VERSION 5.8 ;
BUSBITCHARS "[]" ;
DIVIDERCHAR "/" ;
UNITS
    DATABASE MICRONS 1000 ;
END UNITS

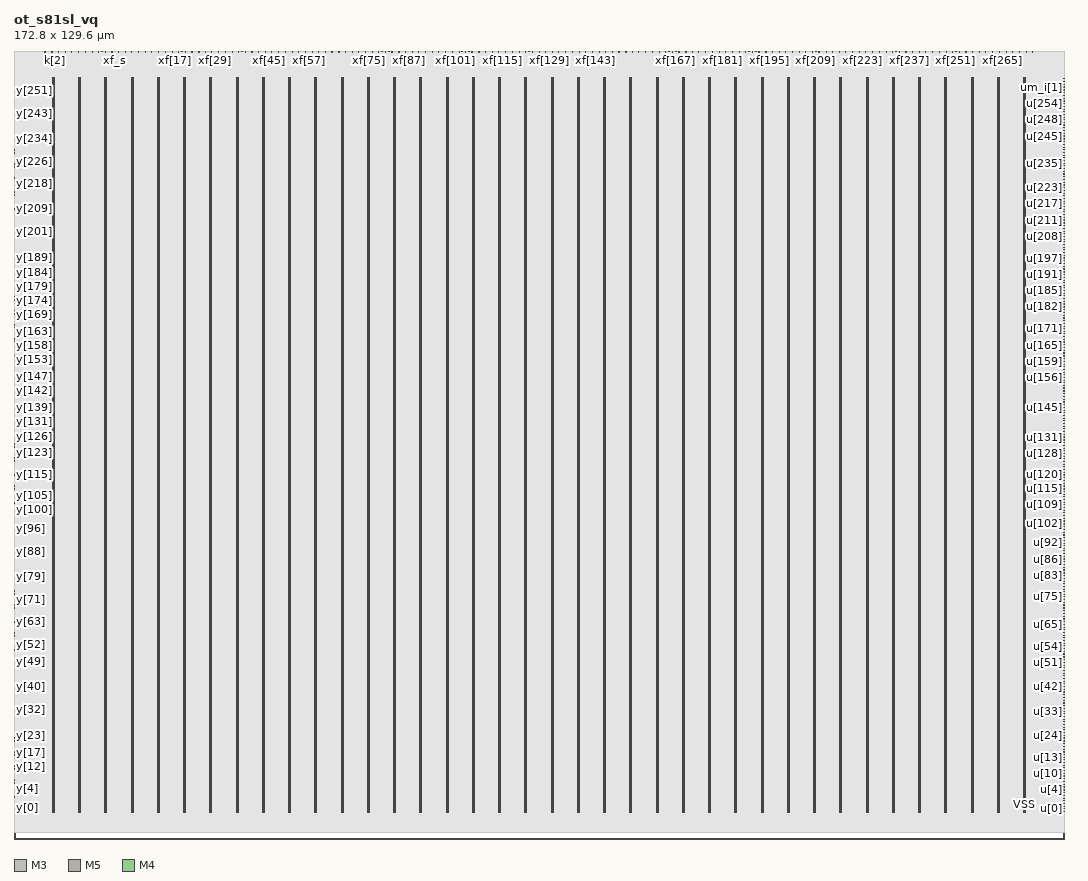
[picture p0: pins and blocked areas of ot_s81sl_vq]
MACRO ot_s81sl_vq
  FOREIGN ot_s81sl_vq 0 0 ;
  CLASS BLOCK ;
  SIZE 172.8 BY 129.6 ;
  PIN clk
    DIRECTION INPUT ;
    USE SIGNAL ;
    PORT
      LAYER M3 ;
        RECT  4.608 129.562 4.626 129.6 ;
    END
  END clk
  PIN fault
    DIRECTION OUTPUT ;
    USE SIGNAL ;
    PORT
      LAYER M3 ;
        RECT  15.552 129.562 15.57 129.6 ;
    END
  END fault
  PIN k[0]
    DIRECTION INPUT ;
    USE SIGNAL ;
    PORT
      LAYER M3 ;
        RECT  5.688 129.562 5.706 129.6 ;
    END
  END k[0]
  PIN k[1]
    DIRECTION INPUT ;
    USE SIGNAL ;
    PORT
      LAYER M5 ;
        RECT  6.24 129.516 6.264 129.6 ;
    END
  END k[1]
  PIN k[2]
    DIRECTION INPUT ;
    USE SIGNAL ;
    PORT
      LAYER M3 ;
        RECT  6.768 129.562 6.786 129.6 ;
    END
  END k[2]
  PIN m_b
    DIRECTION INPUT ;
    USE SIGNAL ;
    PORT
      LAYER M5 ;
        RECT  10.656 129.516 10.68 129.6 ;
    END
  END m_b
  PIN m_i[0]
    DIRECTION INPUT ;
    USE SIGNAL ;
    PORT
      LAYER M3 ;
        RECT  11.16 129.562 11.178 129.6 ;
    END
  END m_i[0]
  PIN m_i[1]
    DIRECTION INPUT ;
    USE SIGNAL ;
    PORT
      LAYER M5 ;
        RECT  11.712 129.516 11.736 129.6 ;
    END
  END m_i[1]
  PIN m_i[2]
    DIRECTION INPUT ;
    USE SIGNAL ;
    PORT
      LAYER M3 ;
        RECT  12.24 129.562 12.258 129.6 ;
    END
  END m_i[2]
  PIN m_i[3]
    DIRECTION INPUT ;
    USE SIGNAL ;
    PORT
      LAYER M5 ;
        RECT  12.864 129.516 12.888 129.6 ;
    END
  END m_i[3]
  PIN m_i[4]
    DIRECTION INPUT ;
    USE SIGNAL ;
    PORT
      LAYER M3 ;
        RECT  13.392 129.562 13.41 129.6 ;
    END
  END m_i[4]
  PIN m_i[5]
    DIRECTION INPUT ;
    USE SIGNAL ;
    PORT
      LAYER M5 ;
        RECT  13.92 129.516 13.944 129.6 ;
    END
  END m_i[5]
  PIN m_i[6]
    DIRECTION INPUT ;
    USE SIGNAL ;
    PORT
      LAYER M3 ;
        RECT  14.472 129.562 14.49 129.6 ;
    END
  END m_i[6]
  PIN m_i[7]
    DIRECTION INPUT ;
    USE SIGNAL ;
    PORT
      LAYER M5 ;
        RECT  14.976 129.516 15 129.6 ;
    END
  END m_i[7]
  PIN m_q
    DIRECTION INPUT ;
    USE SIGNAL ;
    PORT
      LAYER M3 ;
        RECT  10.08 129.562 10.098 129.6 ;
    END
  END m_q
  PIN m_v
    DIRECTION INPUT ;
    USE SIGNAL ;
    PORT
      LAYER M5 ;
        RECT  9.504 129.516 9.528 129.6 ;
    END
  END m_v
  PIN rst_n
    DIRECTION INPUT ;
    USE SIGNAL ;
    PORT
      LAYER M5 ;
        RECT  5.088 129.516 5.112 129.6 ;
    END
  END rst_n
  PIN sid[0]
    DIRECTION INPUT ;
    USE SIGNAL ;
    PORT
      LAYER M5 ;
        RECT  7.296 129.516 7.32 129.6 ;
    END
  END sid[0]
  PIN sid[1]
    DIRECTION INPUT ;
    USE SIGNAL ;
    PORT
      LAYER M3 ;
        RECT  7.848 129.562 7.866 129.6 ;
    END
  END sid[1]
  PIN sid[2]
    DIRECTION INPUT ;
    USE SIGNAL ;
    PORT
      LAYER M5 ;
        RECT  8.448 129.516 8.472 129.6 ;
    END
  END sid[2]
  PIN sid[3]
    DIRECTION INPUT ;
    USE SIGNAL ;
    PORT
      LAYER M3 ;
        RECT  9 129.562 9.018 129.6 ;
    END
  END sid[3]
  PIN u[0]
    DIRECTION INPUT ;
    USE SIGNAL ;
    PORT
      LAYER M4 ;
        RECT  172.716 6.336 172.8 6.36 ;
    END
  END u[0]
  PIN u[100]
    DIRECTION INPUT ;
    USE SIGNAL ;
    PORT
      LAYER M4 ;
        RECT  172.716 50.976 172.8 51 ;
    END
  END u[100]
  PIN u[101]
    DIRECTION INPUT ;
    USE SIGNAL ;
    PORT
      LAYER M4 ;
        RECT  172.716 51.36 172.8 51.384 ;
    END
  END u[101]
  PIN u[102]
    DIRECTION INPUT ;
    USE SIGNAL ;
    PORT
      LAYER M4 ;
        RECT  172.716 51.84 172.8 51.864 ;
    END
  END u[102]
  PIN u[103]
    DIRECTION INPUT ;
    USE SIGNAL ;
    PORT
      LAYER M4 ;
        RECT  172.716 52.32 172.8 52.344 ;
    END
  END u[103]
  PIN u[104]
    DIRECTION INPUT ;
    USE SIGNAL ;
    PORT
      LAYER M4 ;
        RECT  172.716 52.704 172.8 52.728 ;
    END
  END u[104]
  PIN u[105]
    DIRECTION INPUT ;
    USE SIGNAL ;
    PORT
      LAYER M4 ;
        RECT  172.716 53.184 172.8 53.208 ;
    END
  END u[105]
  PIN u[106]
    DIRECTION INPUT ;
    USE SIGNAL ;
    PORT
      LAYER M4 ;
        RECT  172.716 53.664 172.8 53.688 ;
    END
  END u[106]
  PIN u[107]
    DIRECTION INPUT ;
    USE SIGNAL ;
    PORT
      LAYER M4 ;
        RECT  172.716 54.048 172.8 54.072 ;
    END
  END u[107]
  PIN u[108]
    DIRECTION INPUT ;
    USE SIGNAL ;
    PORT
      LAYER M4 ;
        RECT  172.716 54.528 172.8 54.552 ;
    END
  END u[108]
  PIN u[109]
    DIRECTION INPUT ;
    USE SIGNAL ;
    PORT
      LAYER M4 ;
        RECT  172.716 55.008 172.8 55.032 ;
    END
  END u[109]
  PIN u[10]
    DIRECTION INPUT ;
    USE SIGNAL ;
    PORT
      LAYER M4 ;
        RECT  172.716 10.752 172.8 10.776 ;
    END
  END u[10]
  PIN u[110]
    DIRECTION INPUT ;
    USE SIGNAL ;
    PORT
      LAYER M4 ;
        RECT  172.716 55.392 172.8 55.416 ;
    END
  END u[110]
  PIN u[111]
    DIRECTION INPUT ;
    USE SIGNAL ;
    PORT
      LAYER M4 ;
        RECT  172.716 55.872 172.8 55.896 ;
    END
  END u[111]
  PIN u[112]
    DIRECTION INPUT ;
    USE SIGNAL ;
    PORT
      LAYER M4 ;
        RECT  172.716 56.352 172.8 56.376 ;
    END
  END u[112]
  PIN u[113]
    DIRECTION INPUT ;
    USE SIGNAL ;
    PORT
      LAYER M4 ;
        RECT  172.716 56.736 172.8 56.76 ;
    END
  END u[113]
  PIN u[114]
    DIRECTION INPUT ;
    USE SIGNAL ;
    PORT
      LAYER M4 ;
        RECT  172.716 57.216 172.8 57.24 ;
    END
  END u[114]
  PIN u[115]
    DIRECTION INPUT ;
    USE SIGNAL ;
    PORT
      LAYER M4 ;
        RECT  172.716 57.6 172.8 57.624 ;
    END
  END u[115]
  PIN u[116]
    DIRECTION INPUT ;
    USE SIGNAL ;
    PORT
      LAYER M4 ;
        RECT  172.716 58.08 172.8 58.104 ;
    END
  END u[116]
  PIN u[117]
    DIRECTION INPUT ;
    USE SIGNAL ;
    PORT
      LAYER M4 ;
        RECT  172.716 58.56 172.8 58.584 ;
    END
  END u[117]
  PIN u[118]
    DIRECTION INPUT ;
    USE SIGNAL ;
    PORT
      LAYER M4 ;
        RECT  172.716 58.944 172.8 58.968 ;
    END
  END u[118]
  PIN u[119]
    DIRECTION INPUT ;
    USE SIGNAL ;
    PORT
      LAYER M4 ;
        RECT  172.716 59.424 172.8 59.448 ;
    END
  END u[119]
  PIN u[11]
    DIRECTION INPUT ;
    USE SIGNAL ;
    PORT
      LAYER M4 ;
        RECT  172.716 11.232 172.8 11.256 ;
    END
  END u[11]
  PIN u[120]
    DIRECTION INPUT ;
    USE SIGNAL ;
    PORT
      LAYER M4 ;
        RECT  172.716 59.904 172.8 59.928 ;
    END
  END u[120]
  PIN u[121]
    DIRECTION INPUT ;
    USE SIGNAL ;
    PORT
      LAYER M4 ;
        RECT  172.716 60.288 172.8 60.312 ;
    END
  END u[121]
  PIN u[122]
    DIRECTION INPUT ;
    USE SIGNAL ;
    PORT
      LAYER M4 ;
        RECT  172.716 60.768 172.8 60.792 ;
    END
  END u[122]
  PIN u[123]
    DIRECTION INPUT ;
    USE SIGNAL ;
    PORT
      LAYER M4 ;
        RECT  172.716 61.248 172.8 61.272 ;
    END
  END u[123]
  PIN u[124]
    DIRECTION INPUT ;
    USE SIGNAL ;
    PORT
      LAYER M4 ;
        RECT  172.716 61.632 172.8 61.656 ;
    END
  END u[124]
  PIN u[125]
    DIRECTION INPUT ;
    USE SIGNAL ;
    PORT
      LAYER M4 ;
        RECT  172.716 62.112 172.8 62.136 ;
    END
  END u[125]
  PIN u[126]
    DIRECTION INPUT ;
    USE SIGNAL ;
    PORT
      LAYER M4 ;
        RECT  172.716 62.592 172.8 62.616 ;
    END
  END u[126]
  PIN u[127]
    DIRECTION INPUT ;
    USE SIGNAL ;
    PORT
      LAYER M4 ;
        RECT  172.716 62.976 172.8 63 ;
    END
  END u[127]
  PIN u[128]
    DIRECTION INPUT ;
    USE SIGNAL ;
    PORT
      LAYER M4 ;
        RECT  172.716 63.456 172.8 63.48 ;
    END
  END u[128]
  PIN u[129]
    DIRECTION INPUT ;
    USE SIGNAL ;
    PORT
      LAYER M4 ;
        RECT  172.716 63.936 172.8 63.96 ;
    END
  END u[129]
  PIN u[12]
    DIRECTION INPUT ;
    USE SIGNAL ;
    PORT
      LAYER M4 ;
        RECT  172.716 11.712 172.8 11.736 ;
    END
  END u[12]
  PIN u[130]
    DIRECTION INPUT ;
    USE SIGNAL ;
    PORT
      LAYER M4 ;
        RECT  172.716 64.32 172.8 64.344 ;
    END
  END u[130]
  PIN u[131]
    DIRECTION INPUT ;
    USE SIGNAL ;
    PORT
      LAYER M4 ;
        RECT  172.716 64.8 172.8 64.824 ;
    END
  END u[131]
  PIN u[132]
    DIRECTION INPUT ;
    USE SIGNAL ;
    PORT
      LAYER M4 ;
        RECT  172.716 65.28 172.8 65.304 ;
    END
  END u[132]
  PIN u[133]
    DIRECTION INPUT ;
    USE SIGNAL ;
    PORT
      LAYER M4 ;
        RECT  172.716 65.664 172.8 65.688 ;
    END
  END u[133]
  PIN u[134]
    DIRECTION INPUT ;
    USE SIGNAL ;
    PORT
      LAYER M4 ;
        RECT  172.716 66.144 172.8 66.168 ;
    END
  END u[134]
  PIN u[135]
    DIRECTION INPUT ;
    USE SIGNAL ;
    PORT
      LAYER M4 ;
        RECT  172.716 66.528 172.8 66.552 ;
    END
  END u[135]
  PIN u[136]
    DIRECTION INPUT ;
    USE SIGNAL ;
    PORT
      LAYER M4 ;
        RECT  172.716 67.008 172.8 67.032 ;
    END
  END u[136]
  PIN u[137]
    DIRECTION INPUT ;
    USE SIGNAL ;
    PORT
      LAYER M4 ;
        RECT  172.716 67.488 172.8 67.512 ;
    END
  END u[137]
  PIN u[138]
    DIRECTION INPUT ;
    USE SIGNAL ;
    PORT
      LAYER M4 ;
        RECT  172.716 67.872 172.8 67.896 ;
    END
  END u[138]
  PIN u[139]
    DIRECTION INPUT ;
    USE SIGNAL ;
    PORT
      LAYER M4 ;
        RECT  172.716 68.352 172.8 68.376 ;
    END
  END u[139]
  PIN u[13]
    DIRECTION INPUT ;
    USE SIGNAL ;
    PORT
      LAYER M4 ;
        RECT  172.716 12.096 172.8 12.12 ;
    END
  END u[13]
  PIN u[140]
    DIRECTION INPUT ;
    USE SIGNAL ;
    PORT
      LAYER M4 ;
        RECT  172.716 68.832 172.8 68.856 ;
    END
  END u[140]
  PIN u[141]
    DIRECTION INPUT ;
    USE SIGNAL ;
    PORT
      LAYER M4 ;
        RECT  172.716 69.216 172.8 69.24 ;
    END
  END u[141]
  PIN u[142]
    DIRECTION INPUT ;
    USE SIGNAL ;
    PORT
      LAYER M4 ;
        RECT  172.716 69.696 172.8 69.72 ;
    END
  END u[142]
  PIN u[143]
    DIRECTION INPUT ;
    USE SIGNAL ;
    PORT
      LAYER M4 ;
        RECT  172.716 70.176 172.8 70.2 ;
    END
  END u[143]
  PIN u[144]
    DIRECTION INPUT ;
    USE SIGNAL ;
    PORT
      LAYER M4 ;
        RECT  172.716 70.56 172.8 70.584 ;
    END
  END u[144]
  PIN u[145]
    DIRECTION INPUT ;
    USE SIGNAL ;
    PORT
      LAYER M4 ;
        RECT  172.716 71.04 172.8 71.064 ;
    END
  END u[145]
  PIN u[146]
    DIRECTION INPUT ;
    USE SIGNAL ;
    PORT
      LAYER M4 ;
        RECT  172.716 71.52 172.8 71.544 ;
    END
  END u[146]
  PIN u[147]
    DIRECTION INPUT ;
    USE SIGNAL ;
    PORT
      LAYER M4 ;
        RECT  172.716 71.904 172.8 71.928 ;
    END
  END u[147]
  PIN u[148]
    DIRECTION INPUT ;
    USE SIGNAL ;
    PORT
      LAYER M4 ;
        RECT  172.716 72.384 172.8 72.408 ;
    END
  END u[148]
  PIN u[149]
    DIRECTION INPUT ;
    USE SIGNAL ;
    PORT
      LAYER M4 ;
        RECT  172.716 72.864 172.8 72.888 ;
    END
  END u[149]
  PIN u[14]
    DIRECTION INPUT ;
    USE SIGNAL ;
    PORT
      LAYER M4 ;
        RECT  172.716 12.576 172.8 12.6 ;
    END
  END u[14]
  PIN u[150]
    DIRECTION INPUT ;
    USE SIGNAL ;
    PORT
      LAYER M4 ;
        RECT  172.716 73.248 172.8 73.272 ;
    END
  END u[150]
  PIN u[151]
    DIRECTION INPUT ;
    USE SIGNAL ;
    PORT
      LAYER M4 ;
        RECT  172.716 73.728 172.8 73.752 ;
    END
  END u[151]
  PIN u[152]
    DIRECTION INPUT ;
    USE SIGNAL ;
    PORT
      LAYER M4 ;
        RECT  172.716 74.208 172.8 74.232 ;
    END
  END u[152]
  PIN u[153]
    DIRECTION INPUT ;
    USE SIGNAL ;
    PORT
      LAYER M4 ;
        RECT  172.716 74.592 172.8 74.616 ;
    END
  END u[153]
  PIN u[154]
    DIRECTION INPUT ;
    USE SIGNAL ;
    PORT
      LAYER M4 ;
        RECT  172.716 75.072 172.8 75.096 ;
    END
  END u[154]
  PIN u[155]
    DIRECTION INPUT ;
    USE SIGNAL ;
    PORT
      LAYER M4 ;
        RECT  172.716 75.456 172.8 75.48 ;
    END
  END u[155]
  PIN u[156]
    DIRECTION INPUT ;
    USE SIGNAL ;
    PORT
      LAYER M4 ;
        RECT  172.716 75.936 172.8 75.96 ;
    END
  END u[156]
  PIN u[157]
    DIRECTION INPUT ;
    USE SIGNAL ;
    PORT
      LAYER M4 ;
        RECT  172.716 76.416 172.8 76.44 ;
    END
  END u[157]
  PIN u[158]
    DIRECTION INPUT ;
    USE SIGNAL ;
    PORT
      LAYER M4 ;
        RECT  172.716 76.8 172.8 76.824 ;
    END
  END u[158]
  PIN u[159]
    DIRECTION INPUT ;
    USE SIGNAL ;
    PORT
      LAYER M4 ;
        RECT  172.716 77.28 172.8 77.304 ;
    END
  END u[159]
  PIN u[15]
    DIRECTION INPUT ;
    USE SIGNAL ;
    PORT
      LAYER M4 ;
        RECT  172.716 13.056 172.8 13.08 ;
    END
  END u[15]
  PIN u[160]
    DIRECTION INPUT ;
    USE SIGNAL ;
    PORT
      LAYER M4 ;
        RECT  172.716 77.76 172.8 77.784 ;
    END
  END u[160]
  PIN u[161]
    DIRECTION INPUT ;
    USE SIGNAL ;
    PORT
      LAYER M4 ;
        RECT  172.716 78.144 172.8 78.168 ;
    END
  END u[161]
  PIN u[162]
    DIRECTION INPUT ;
    USE SIGNAL ;
    PORT
      LAYER M4 ;
        RECT  172.716 78.624 172.8 78.648 ;
    END
  END u[162]
  PIN u[163]
    DIRECTION INPUT ;
    USE SIGNAL ;
    PORT
      LAYER M4 ;
        RECT  172.716 79.104 172.8 79.128 ;
    END
  END u[163]
  PIN u[164]
    DIRECTION INPUT ;
    USE SIGNAL ;
    PORT
      LAYER M4 ;
        RECT  172.716 79.488 172.8 79.512 ;
    END
  END u[164]
  PIN u[165]
    DIRECTION INPUT ;
    USE SIGNAL ;
    PORT
      LAYER M4 ;
        RECT  172.716 79.968 172.8 79.992 ;
    END
  END u[165]
  PIN u[166]
    DIRECTION INPUT ;
    USE SIGNAL ;
    PORT
      LAYER M4 ;
        RECT  172.716 80.448 172.8 80.472 ;
    END
  END u[166]
  PIN u[167]
    DIRECTION INPUT ;
    USE SIGNAL ;
    PORT
      LAYER M4 ;
        RECT  172.716 80.832 172.8 80.856 ;
    END
  END u[167]
  PIN u[168]
    DIRECTION INPUT ;
    USE SIGNAL ;
    PORT
      LAYER M4 ;
        RECT  172.716 81.312 172.8 81.336 ;
    END
  END u[168]
  PIN u[169]
    DIRECTION INPUT ;
    USE SIGNAL ;
    PORT
      LAYER M4 ;
        RECT  172.716 81.792 172.8 81.816 ;
    END
  END u[169]
  PIN u[16]
    DIRECTION INPUT ;
    USE SIGNAL ;
    PORT
      LAYER M4 ;
        RECT  172.716 13.44 172.8 13.464 ;
    END
  END u[16]
  PIN u[170]
    DIRECTION INPUT ;
    USE SIGNAL ;
    PORT
      LAYER M4 ;
        RECT  172.716 82.176 172.8 82.2 ;
    END
  END u[170]
  PIN u[171]
    DIRECTION INPUT ;
    USE SIGNAL ;
    PORT
      LAYER M4 ;
        RECT  172.716 82.656 172.8 82.68 ;
    END
  END u[171]
  PIN u[172]
    DIRECTION INPUT ;
    USE SIGNAL ;
    PORT
      LAYER M4 ;
        RECT  172.716 83.136 172.8 83.16 ;
    END
  END u[172]
  PIN u[173]
    DIRECTION INPUT ;
    USE SIGNAL ;
    PORT
      LAYER M4 ;
        RECT  172.716 83.52 172.8 83.544 ;
    END
  END u[173]
  PIN u[174]
    DIRECTION INPUT ;
    USE SIGNAL ;
    PORT
      LAYER M4 ;
        RECT  172.716 84 172.8 84.024 ;
    END
  END u[174]
  PIN u[175]
    DIRECTION INPUT ;
    USE SIGNAL ;
    PORT
      LAYER M4 ;
        RECT  172.716 84.384 172.8 84.408 ;
    END
  END u[175]
  PIN u[176]
    DIRECTION INPUT ;
    USE SIGNAL ;
    PORT
      LAYER M4 ;
        RECT  172.716 84.864 172.8 84.888 ;
    END
  END u[176]
  PIN u[177]
    DIRECTION INPUT ;
    USE SIGNAL ;
    PORT
      LAYER M4 ;
        RECT  172.716 85.344 172.8 85.368 ;
    END
  END u[177]
  PIN u[178]
    DIRECTION INPUT ;
    USE SIGNAL ;
    PORT
      LAYER M4 ;
        RECT  172.716 85.728 172.8 85.752 ;
    END
  END u[178]
  PIN u[179]
    DIRECTION INPUT ;
    USE SIGNAL ;
    PORT
      LAYER M4 ;
        RECT  172.716 86.208 172.8 86.232 ;
    END
  END u[179]
  PIN u[17]
    DIRECTION INPUT ;
    USE SIGNAL ;
    PORT
      LAYER M4 ;
        RECT  172.716 13.92 172.8 13.944 ;
    END
  END u[17]
  PIN u[180]
    DIRECTION INPUT ;
    USE SIGNAL ;
    PORT
      LAYER M4 ;
        RECT  172.716 86.688 172.8 86.712 ;
    END
  END u[180]
  PIN u[181]
    DIRECTION INPUT ;
    USE SIGNAL ;
    PORT
      LAYER M4 ;
        RECT  172.716 87.072 172.8 87.096 ;
    END
  END u[181]
  PIN u[182]
    DIRECTION INPUT ;
    USE SIGNAL ;
    PORT
      LAYER M4 ;
        RECT  172.716 87.552 172.8 87.576 ;
    END
  END u[182]
  PIN u[183]
    DIRECTION INPUT ;
    USE SIGNAL ;
    PORT
      LAYER M4 ;
        RECT  172.716 88.032 172.8 88.056 ;
    END
  END u[183]
  PIN u[184]
    DIRECTION INPUT ;
    USE SIGNAL ;
    PORT
      LAYER M4 ;
        RECT  172.716 88.416 172.8 88.44 ;
    END
  END u[184]
  PIN u[185]
    DIRECTION INPUT ;
    USE SIGNAL ;
    PORT
      LAYER M4 ;
        RECT  172.716 88.896 172.8 88.92 ;
    END
  END u[185]
  PIN u[186]
    DIRECTION INPUT ;
    USE SIGNAL ;
    PORT
      LAYER M4 ;
        RECT  172.716 89.376 172.8 89.4 ;
    END
  END u[186]
  PIN u[187]
    DIRECTION INPUT ;
    USE SIGNAL ;
    PORT
      LAYER M4 ;
        RECT  172.716 89.76 172.8 89.784 ;
    END
  END u[187]
  PIN u[188]
    DIRECTION INPUT ;
    USE SIGNAL ;
    PORT
      LAYER M4 ;
        RECT  172.716 90.24 172.8 90.264 ;
    END
  END u[188]
  PIN u[189]
    DIRECTION INPUT ;
    USE SIGNAL ;
    PORT
      LAYER M4 ;
        RECT  172.716 90.72 172.8 90.744 ;
    END
  END u[189]
  PIN u[18]
    DIRECTION INPUT ;
    USE SIGNAL ;
    PORT
      LAYER M4 ;
        RECT  172.716 14.304 172.8 14.328 ;
    END
  END u[18]
  PIN u[190]
    DIRECTION INPUT ;
    USE SIGNAL ;
    PORT
      LAYER M4 ;
        RECT  172.716 91.104 172.8 91.128 ;
    END
  END u[190]
  PIN u[191]
    DIRECTION INPUT ;
    USE SIGNAL ;
    PORT
      LAYER M4 ;
        RECT  172.716 91.584 172.8 91.608 ;
    END
  END u[191]
  PIN u[192]
    DIRECTION INPUT ;
    USE SIGNAL ;
    PORT
      LAYER M4 ;
        RECT  172.716 91.968 172.8 91.992 ;
    END
  END u[192]
  PIN u[193]
    DIRECTION INPUT ;
    USE SIGNAL ;
    PORT
      LAYER M4 ;
        RECT  172.716 92.448 172.8 92.472 ;
    END
  END u[193]
  PIN u[194]
    DIRECTION INPUT ;
    USE SIGNAL ;
    PORT
      LAYER M4 ;
        RECT  172.716 92.928 172.8 92.952 ;
    END
  END u[194]
  PIN u[195]
    DIRECTION INPUT ;
    USE SIGNAL ;
    PORT
      LAYER M4 ;
        RECT  172.716 93.312 172.8 93.336 ;
    END
  END u[195]
  PIN u[196]
    DIRECTION INPUT ;
    USE SIGNAL ;
    PORT
      LAYER M4 ;
        RECT  172.716 93.792 172.8 93.816 ;
    END
  END u[196]
  PIN u[197]
    DIRECTION INPUT ;
    USE SIGNAL ;
    PORT
      LAYER M4 ;
        RECT  172.716 94.272 172.8 94.296 ;
    END
  END u[197]
  PIN u[198]
    DIRECTION INPUT ;
    USE SIGNAL ;
    PORT
      LAYER M4 ;
        RECT  172.716 94.656 172.8 94.68 ;
    END
  END u[198]
  PIN u[199]
    DIRECTION INPUT ;
    USE SIGNAL ;
    PORT
      LAYER M4 ;
        RECT  172.716 95.136 172.8 95.16 ;
    END
  END u[199]
  PIN u[19]
    DIRECTION INPUT ;
    USE SIGNAL ;
    PORT
      LAYER M4 ;
        RECT  172.716 14.784 172.8 14.808 ;
    END
  END u[19]
  PIN u[1]
    DIRECTION INPUT ;
    USE SIGNAL ;
    PORT
      LAYER M4 ;
        RECT  172.716 6.72 172.8 6.744 ;
    END
  END u[1]
  PIN u[200]
    DIRECTION INPUT ;
    USE SIGNAL ;
    PORT
      LAYER M4 ;
        RECT  172.716 95.616 172.8 95.64 ;
    END
  END u[200]
  PIN u[201]
    DIRECTION INPUT ;
    USE SIGNAL ;
    PORT
      LAYER M4 ;
        RECT  172.716 96 172.8 96.024 ;
    END
  END u[201]
  PIN u[202]
    DIRECTION INPUT ;
    USE SIGNAL ;
    PORT
      LAYER M4 ;
        RECT  172.716 96.48 172.8 96.504 ;
    END
  END u[202]
  PIN u[203]
    DIRECTION INPUT ;
    USE SIGNAL ;
    PORT
      LAYER M4 ;
        RECT  172.716 96.96 172.8 96.984 ;
    END
  END u[203]
  PIN u[204]
    DIRECTION INPUT ;
    USE SIGNAL ;
    PORT
      LAYER M4 ;
        RECT  172.716 97.344 172.8 97.368 ;
    END
  END u[204]
  PIN u[205]
    DIRECTION INPUT ;
    USE SIGNAL ;
    PORT
      LAYER M4 ;
        RECT  172.716 97.824 172.8 97.848 ;
    END
  END u[205]
  PIN u[206]
    DIRECTION INPUT ;
    USE SIGNAL ;
    PORT
      LAYER M4 ;
        RECT  172.716 98.304 172.8 98.328 ;
    END
  END u[206]
  PIN u[207]
    DIRECTION INPUT ;
    USE SIGNAL ;
    PORT
      LAYER M4 ;
        RECT  172.716 98.688 172.8 98.712 ;
    END
  END u[207]
  PIN u[208]
    DIRECTION INPUT ;
    USE SIGNAL ;
    PORT
      LAYER M4 ;
        RECT  172.716 99.168 172.8 99.192 ;
    END
  END u[208]
  PIN u[209]
    DIRECTION INPUT ;
    USE SIGNAL ;
    PORT
      LAYER M4 ;
        RECT  172.716 99.648 172.8 99.672 ;
    END
  END u[209]
  PIN u[20]
    DIRECTION INPUT ;
    USE SIGNAL ;
    PORT
      LAYER M4 ;
        RECT  172.716 15.264 172.8 15.288 ;
    END
  END u[20]
  PIN u[210]
    DIRECTION INPUT ;
    USE SIGNAL ;
    PORT
      LAYER M4 ;
        RECT  172.716 100.032 172.8 100.056 ;
    END
  END u[210]
  PIN u[211]
    DIRECTION INPUT ;
    USE SIGNAL ;
    PORT
      LAYER M4 ;
        RECT  172.716 100.512 172.8 100.536 ;
    END
  END u[211]
  PIN u[212]
    DIRECTION INPUT ;
    USE SIGNAL ;
    PORT
      LAYER M4 ;
        RECT  172.716 100.896 172.8 100.92 ;
    END
  END u[212]
  PIN u[213]
    DIRECTION INPUT ;
    USE SIGNAL ;
    PORT
      LAYER M4 ;
        RECT  172.716 101.376 172.8 101.4 ;
    END
  END u[213]
  PIN u[214]
    DIRECTION INPUT ;
    USE SIGNAL ;
    PORT
      LAYER M4 ;
        RECT  172.716 101.856 172.8 101.88 ;
    END
  END u[214]
  PIN u[215]
    DIRECTION INPUT ;
    USE SIGNAL ;
    PORT
      LAYER M4 ;
        RECT  172.716 102.24 172.8 102.264 ;
    END
  END u[215]
  PIN u[216]
    DIRECTION INPUT ;
    USE SIGNAL ;
    PORT
      LAYER M4 ;
        RECT  172.716 102.72 172.8 102.744 ;
    END
  END u[216]
  PIN u[217]
    DIRECTION INPUT ;
    USE SIGNAL ;
    PORT
      LAYER M4 ;
        RECT  172.716 103.2 172.8 103.224 ;
    END
  END u[217]
  PIN u[218]
    DIRECTION INPUT ;
    USE SIGNAL ;
    PORT
      LAYER M4 ;
        RECT  172.716 103.584 172.8 103.608 ;
    END
  END u[218]
  PIN u[219]
    DIRECTION INPUT ;
    USE SIGNAL ;
    PORT
      LAYER M4 ;
        RECT  172.716 104.064 172.8 104.088 ;
    END
  END u[219]
  PIN u[21]
    DIRECTION INPUT ;
    USE SIGNAL ;
    PORT
      LAYER M4 ;
        RECT  172.716 15.648 172.8 15.672 ;
    END
  END u[21]
  PIN u[220]
    DIRECTION INPUT ;
    USE SIGNAL ;
    PORT
      LAYER M4 ;
        RECT  172.716 104.544 172.8 104.568 ;
    END
  END u[220]
  PIN u[221]
    DIRECTION INPUT ;
    USE SIGNAL ;
    PORT
      LAYER M4 ;
        RECT  172.716 104.928 172.8 104.952 ;
    END
  END u[221]
  PIN u[222]
    DIRECTION INPUT ;
    USE SIGNAL ;
    PORT
      LAYER M4 ;
        RECT  172.716 105.408 172.8 105.432 ;
    END
  END u[222]
  PIN u[223]
    DIRECTION INPUT ;
    USE SIGNAL ;
    PORT
      LAYER M4 ;
        RECT  172.716 105.888 172.8 105.912 ;
    END
  END u[223]
  PIN u[224]
    DIRECTION INPUT ;
    USE SIGNAL ;
    PORT
      LAYER M4 ;
        RECT  172.716 106.272 172.8 106.296 ;
    END
  END u[224]
  PIN u[225]
    DIRECTION INPUT ;
    USE SIGNAL ;
    PORT
      LAYER M4 ;
        RECT  172.716 106.752 172.8 106.776 ;
    END
  END u[225]
  PIN u[226]
    DIRECTION INPUT ;
    USE SIGNAL ;
    PORT
      LAYER M4 ;
        RECT  172.716 107.232 172.8 107.256 ;
    END
  END u[226]
  PIN u[227]
    DIRECTION INPUT ;
    USE SIGNAL ;
    PORT
      LAYER M4 ;
        RECT  172.716 107.616 172.8 107.64 ;
    END
  END u[227]
  PIN u[228]
    DIRECTION INPUT ;
    USE SIGNAL ;
    PORT
      LAYER M4 ;
        RECT  172.716 108.096 172.8 108.12 ;
    END
  END u[228]
  PIN u[229]
    DIRECTION INPUT ;
    USE SIGNAL ;
    PORT
      LAYER M4 ;
        RECT  172.716 108.576 172.8 108.6 ;
    END
  END u[229]
  PIN u[22]
    DIRECTION INPUT ;
    USE SIGNAL ;
    PORT
      LAYER M4 ;
        RECT  172.716 16.128 172.8 16.152 ;
    END
  END u[22]
  PIN u[230]
    DIRECTION INPUT ;
    USE SIGNAL ;
    PORT
      LAYER M4 ;
        RECT  172.716 108.96 172.8 108.984 ;
    END
  END u[230]
  PIN u[231]
    DIRECTION INPUT ;
    USE SIGNAL ;
    PORT
      LAYER M4 ;
        RECT  172.716 109.44 172.8 109.464 ;
    END
  END u[231]
  PIN u[232]
    DIRECTION INPUT ;
    USE SIGNAL ;
    PORT
      LAYER M4 ;
        RECT  172.716 109.824 172.8 109.848 ;
    END
  END u[232]
  PIN u[233]
    DIRECTION INPUT ;
    USE SIGNAL ;
    PORT
      LAYER M4 ;
        RECT  172.716 110.304 172.8 110.328 ;
    END
  END u[233]
  PIN u[234]
    DIRECTION INPUT ;
    USE SIGNAL ;
    PORT
      LAYER M4 ;
        RECT  172.716 110.784 172.8 110.808 ;
    END
  END u[234]
  PIN u[235]
    DIRECTION INPUT ;
    USE SIGNAL ;
    PORT
      LAYER M4 ;
        RECT  172.716 111.168 172.8 111.192 ;
    END
  END u[235]
  PIN u[236]
    DIRECTION INPUT ;
    USE SIGNAL ;
    PORT
      LAYER M4 ;
        RECT  172.716 111.648 172.8 111.672 ;
    END
  END u[236]
  PIN u[237]
    DIRECTION INPUT ;
    USE SIGNAL ;
    PORT
      LAYER M4 ;
        RECT  172.716 112.128 172.8 112.152 ;
    END
  END u[237]
  PIN u[238]
    DIRECTION INPUT ;
    USE SIGNAL ;
    PORT
      LAYER M4 ;
        RECT  172.716 112.512 172.8 112.536 ;
    END
  END u[238]
  PIN u[239]
    DIRECTION INPUT ;
    USE SIGNAL ;
    PORT
      LAYER M4 ;
        RECT  172.716 112.992 172.8 113.016 ;
    END
  END u[239]
  PIN u[23]
    DIRECTION INPUT ;
    USE SIGNAL ;
    PORT
      LAYER M4 ;
        RECT  172.716 16.608 172.8 16.632 ;
    END
  END u[23]
  PIN u[240]
    DIRECTION INPUT ;
    USE SIGNAL ;
    PORT
      LAYER M4 ;
        RECT  172.716 113.472 172.8 113.496 ;
    END
  END u[240]
  PIN u[241]
    DIRECTION INPUT ;
    USE SIGNAL ;
    PORT
      LAYER M4 ;
        RECT  172.716 113.856 172.8 113.88 ;
    END
  END u[241]
  PIN u[242]
    DIRECTION INPUT ;
    USE SIGNAL ;
    PORT
      LAYER M4 ;
        RECT  172.716 114.336 172.8 114.36 ;
    END
  END u[242]
  PIN u[243]
    DIRECTION INPUT ;
    USE SIGNAL ;
    PORT
      LAYER M4 ;
        RECT  172.716 114.816 172.8 114.84 ;
    END
  END u[243]
  PIN u[244]
    DIRECTION INPUT ;
    USE SIGNAL ;
    PORT
      LAYER M4 ;
        RECT  172.716 115.2 172.8 115.224 ;
    END
  END u[244]
  PIN u[245]
    DIRECTION INPUT ;
    USE SIGNAL ;
    PORT
      LAYER M4 ;
        RECT  172.716 115.68 172.8 115.704 ;
    END
  END u[245]
  PIN u[246]
    DIRECTION INPUT ;
    USE SIGNAL ;
    PORT
      LAYER M4 ;
        RECT  172.716 116.16 172.8 116.184 ;
    END
  END u[246]
  PIN u[247]
    DIRECTION INPUT ;
    USE SIGNAL ;
    PORT
      LAYER M4 ;
        RECT  172.716 116.544 172.8 116.568 ;
    END
  END u[247]
  PIN u[248]
    DIRECTION INPUT ;
    USE SIGNAL ;
    PORT
      LAYER M4 ;
        RECT  172.716 117.024 172.8 117.048 ;
    END
  END u[248]
  PIN u[249]
    DIRECTION INPUT ;
    USE SIGNAL ;
    PORT
      LAYER M4 ;
        RECT  172.716 117.504 172.8 117.528 ;
    END
  END u[249]
  PIN u[24]
    DIRECTION INPUT ;
    USE SIGNAL ;
    PORT
      LAYER M4 ;
        RECT  172.716 16.992 172.8 17.016 ;
    END
  END u[24]
  PIN u[250]
    DIRECTION INPUT ;
    USE SIGNAL ;
    PORT
      LAYER M4 ;
        RECT  172.716 117.888 172.8 117.912 ;
    END
  END u[250]
  PIN u[251]
    DIRECTION INPUT ;
    USE SIGNAL ;
    PORT
      LAYER M4 ;
        RECT  172.716 118.368 172.8 118.392 ;
    END
  END u[251]
  PIN u[252]
    DIRECTION INPUT ;
    USE SIGNAL ;
    PORT
      LAYER M4 ;
        RECT  172.716 118.752 172.8 118.776 ;
    END
  END u[252]
  PIN u[253]
    DIRECTION INPUT ;
    USE SIGNAL ;
    PORT
      LAYER M4 ;
        RECT  172.716 119.232 172.8 119.256 ;
    END
  END u[253]
  PIN u[254]
    DIRECTION INPUT ;
    USE SIGNAL ;
    PORT
      LAYER M4 ;
        RECT  172.716 119.712 172.8 119.736 ;
    END
  END u[254]
  PIN u[255]
    DIRECTION INPUT ;
    USE SIGNAL ;
    PORT
      LAYER M4 ;
        RECT  172.716 120.096 172.8 120.12 ;
    END
  END u[255]
  PIN u[25]
    DIRECTION INPUT ;
    USE SIGNAL ;
    PORT
      LAYER M4 ;
        RECT  172.716 17.472 172.8 17.496 ;
    END
  END u[25]
  PIN u[26]
    DIRECTION INPUT ;
    USE SIGNAL ;
    PORT
      LAYER M4 ;
        RECT  172.716 17.952 172.8 17.976 ;
    END
  END u[26]
  PIN u[27]
    DIRECTION INPUT ;
    USE SIGNAL ;
    PORT
      LAYER M4 ;
        RECT  172.716 18.336 172.8 18.36 ;
    END
  END u[27]
  PIN u[28]
    DIRECTION INPUT ;
    USE SIGNAL ;
    PORT
      LAYER M4 ;
        RECT  172.716 18.816 172.8 18.84 ;
    END
  END u[28]
  PIN u[29]
    DIRECTION INPUT ;
    USE SIGNAL ;
    PORT
      LAYER M4 ;
        RECT  172.716 19.296 172.8 19.32 ;
    END
  END u[29]
  PIN u[2]
    DIRECTION INPUT ;
    USE SIGNAL ;
    PORT
      LAYER M4 ;
        RECT  172.716 7.2 172.8 7.224 ;
    END
  END u[2]
  PIN u[30]
    DIRECTION INPUT ;
    USE SIGNAL ;
    PORT
      LAYER M4 ;
        RECT  172.716 19.68 172.8 19.704 ;
    END
  END u[30]
  PIN u[31]
    DIRECTION INPUT ;
    USE SIGNAL ;
    PORT
      LAYER M4 ;
        RECT  172.716 20.16 172.8 20.184 ;
    END
  END u[31]
  PIN u[32]
    DIRECTION INPUT ;
    USE SIGNAL ;
    PORT
      LAYER M4 ;
        RECT  172.716 20.64 172.8 20.664 ;
    END
  END u[32]
  PIN u[33]
    DIRECTION INPUT ;
    USE SIGNAL ;
    PORT
      LAYER M4 ;
        RECT  172.716 21.024 172.8 21.048 ;
    END
  END u[33]
  PIN u[34]
    DIRECTION INPUT ;
    USE SIGNAL ;
    PORT
      LAYER M4 ;
        RECT  172.716 21.504 172.8 21.528 ;
    END
  END u[34]
  PIN u[35]
    DIRECTION INPUT ;
    USE SIGNAL ;
    PORT
      LAYER M4 ;
        RECT  172.716 21.984 172.8 22.008 ;
    END
  END u[35]
  PIN u[36]
    DIRECTION INPUT ;
    USE SIGNAL ;
    PORT
      LAYER M4 ;
        RECT  172.716 22.368 172.8 22.392 ;
    END
  END u[36]
  PIN u[37]
    DIRECTION INPUT ;
    USE SIGNAL ;
    PORT
      LAYER M4 ;
        RECT  172.716 22.848 172.8 22.872 ;
    END
  END u[37]
  PIN u[38]
    DIRECTION INPUT ;
    USE SIGNAL ;
    PORT
      LAYER M4 ;
        RECT  172.716 23.232 172.8 23.256 ;
    END
  END u[38]
  PIN u[39]
    DIRECTION INPUT ;
    USE SIGNAL ;
    PORT
      LAYER M4 ;
        RECT  172.716 23.712 172.8 23.736 ;
    END
  END u[39]
  PIN u[3]
    DIRECTION INPUT ;
    USE SIGNAL ;
    PORT
      LAYER M4 ;
        RECT  172.716 7.68 172.8 7.704 ;
    END
  END u[3]
  PIN u[40]
    DIRECTION INPUT ;
    USE SIGNAL ;
    PORT
      LAYER M4 ;
        RECT  172.716 24.192 172.8 24.216 ;
    END
  END u[40]
  PIN u[41]
    DIRECTION INPUT ;
    USE SIGNAL ;
    PORT
      LAYER M4 ;
        RECT  172.716 24.576 172.8 24.6 ;
    END
  END u[41]
  PIN u[42]
    DIRECTION INPUT ;
    USE SIGNAL ;
    PORT
      LAYER M4 ;
        RECT  172.716 25.056 172.8 25.08 ;
    END
  END u[42]
  PIN u[43]
    DIRECTION INPUT ;
    USE SIGNAL ;
    PORT
      LAYER M4 ;
        RECT  172.716 25.536 172.8 25.56 ;
    END
  END u[43]
  PIN u[44]
    DIRECTION INPUT ;
    USE SIGNAL ;
    PORT
      LAYER M4 ;
        RECT  172.716 25.92 172.8 25.944 ;
    END
  END u[44]
  PIN u[45]
    DIRECTION INPUT ;
    USE SIGNAL ;
    PORT
      LAYER M4 ;
        RECT  172.716 26.4 172.8 26.424 ;
    END
  END u[45]
  PIN u[46]
    DIRECTION INPUT ;
    USE SIGNAL ;
    PORT
      LAYER M4 ;
        RECT  172.716 26.88 172.8 26.904 ;
    END
  END u[46]
  PIN u[47]
    DIRECTION INPUT ;
    USE SIGNAL ;
    PORT
      LAYER M4 ;
        RECT  172.716 27.264 172.8 27.288 ;
    END
  END u[47]
  PIN u[48]
    DIRECTION INPUT ;
    USE SIGNAL ;
    PORT
      LAYER M4 ;
        RECT  172.716 27.744 172.8 27.768 ;
    END
  END u[48]
  PIN u[49]
    DIRECTION INPUT ;
    USE SIGNAL ;
    PORT
      LAYER M4 ;
        RECT  172.716 28.224 172.8 28.248 ;
    END
  END u[49]
  PIN u[4]
    DIRECTION INPUT ;
    USE SIGNAL ;
    PORT
      LAYER M4 ;
        RECT  172.716 8.064 172.8 8.088 ;
    END
  END u[4]
  PIN u[50]
    DIRECTION INPUT ;
    USE SIGNAL ;
    PORT
      LAYER M4 ;
        RECT  172.716 28.608 172.8 28.632 ;
    END
  END u[50]
  PIN u[51]
    DIRECTION INPUT ;
    USE SIGNAL ;
    PORT
      LAYER M4 ;
        RECT  172.716 29.088 172.8 29.112 ;
    END
  END u[51]
  PIN u[52]
    DIRECTION INPUT ;
    USE SIGNAL ;
    PORT
      LAYER M4 ;
        RECT  172.716 29.568 172.8 29.592 ;
    END
  END u[52]
  PIN u[53]
    DIRECTION INPUT ;
    USE SIGNAL ;
    PORT
      LAYER M4 ;
        RECT  172.716 29.952 172.8 29.976 ;
    END
  END u[53]
  PIN u[54]
    DIRECTION INPUT ;
    USE SIGNAL ;
    PORT
      LAYER M4 ;
        RECT  172.716 30.432 172.8 30.456 ;
    END
  END u[54]
  PIN u[55]
    DIRECTION INPUT ;
    USE SIGNAL ;
    PORT
      LAYER M4 ;
        RECT  172.716 30.912 172.8 30.936 ;
    END
  END u[55]
  PIN u[56]
    DIRECTION INPUT ;
    USE SIGNAL ;
    PORT
      LAYER M4 ;
        RECT  172.716 31.296 172.8 31.32 ;
    END
  END u[56]
  PIN u[57]
    DIRECTION INPUT ;
    USE SIGNAL ;
    PORT
      LAYER M4 ;
        RECT  172.716 31.776 172.8 31.8 ;
    END
  END u[57]
  PIN u[58]
    DIRECTION INPUT ;
    USE SIGNAL ;
    PORT
      LAYER M4 ;
        RECT  172.716 32.16 172.8 32.184 ;
    END
  END u[58]
  PIN u[59]
    DIRECTION INPUT ;
    USE SIGNAL ;
    PORT
      LAYER M4 ;
        RECT  172.716 32.64 172.8 32.664 ;
    END
  END u[59]
  PIN u[5]
    DIRECTION INPUT ;
    USE SIGNAL ;
    PORT
      LAYER M4 ;
        RECT  172.716 8.544 172.8 8.568 ;
    END
  END u[5]
  PIN u[60]
    DIRECTION INPUT ;
    USE SIGNAL ;
    PORT
      LAYER M4 ;
        RECT  172.716 33.12 172.8 33.144 ;
    END
  END u[60]
  PIN u[61]
    DIRECTION INPUT ;
    USE SIGNAL ;
    PORT
      LAYER M4 ;
        RECT  172.716 33.504 172.8 33.528 ;
    END
  END u[61]
  PIN u[62]
    DIRECTION INPUT ;
    USE SIGNAL ;
    PORT
      LAYER M4 ;
        RECT  172.716 33.984 172.8 34.008 ;
    END
  END u[62]
  PIN u[63]
    DIRECTION INPUT ;
    USE SIGNAL ;
    PORT
      LAYER M4 ;
        RECT  172.716 34.464 172.8 34.488 ;
    END
  END u[63]
  PIN u[64]
    DIRECTION INPUT ;
    USE SIGNAL ;
    PORT
      LAYER M4 ;
        RECT  172.716 34.848 172.8 34.872 ;
    END
  END u[64]
  PIN u[65]
    DIRECTION INPUT ;
    USE SIGNAL ;
    PORT
      LAYER M4 ;
        RECT  172.716 35.328 172.8 35.352 ;
    END
  END u[65]
  PIN u[66]
    DIRECTION INPUT ;
    USE SIGNAL ;
    PORT
      LAYER M4 ;
        RECT  172.716 35.808 172.8 35.832 ;
    END
  END u[66]
  PIN u[67]
    DIRECTION INPUT ;
    USE SIGNAL ;
    PORT
      LAYER M4 ;
        RECT  172.716 36.192 172.8 36.216 ;
    END
  END u[67]
  PIN u[68]
    DIRECTION INPUT ;
    USE SIGNAL ;
    PORT
      LAYER M4 ;
        RECT  172.716 36.672 172.8 36.696 ;
    END
  END u[68]
  PIN u[69]
    DIRECTION INPUT ;
    USE SIGNAL ;
    PORT
      LAYER M4 ;
        RECT  172.716 37.152 172.8 37.176 ;
    END
  END u[69]
  PIN u[6]
    DIRECTION INPUT ;
    USE SIGNAL ;
    PORT
      LAYER M4 ;
        RECT  172.716 9.024 172.8 9.048 ;
    END
  END u[6]
  PIN u[70]
    DIRECTION INPUT ;
    USE SIGNAL ;
    PORT
      LAYER M4 ;
        RECT  172.716 37.536 172.8 37.56 ;
    END
  END u[70]
  PIN u[71]
    DIRECTION INPUT ;
    USE SIGNAL ;
    PORT
      LAYER M4 ;
        RECT  172.716 38.016 172.8 38.04 ;
    END
  END u[71]
  PIN u[72]
    DIRECTION INPUT ;
    USE SIGNAL ;
    PORT
      LAYER M4 ;
        RECT  172.716 38.496 172.8 38.52 ;
    END
  END u[72]
  PIN u[73]
    DIRECTION INPUT ;
    USE SIGNAL ;
    PORT
      LAYER M4 ;
        RECT  172.716 38.88 172.8 38.904 ;
    END
  END u[73]
  PIN u[74]
    DIRECTION INPUT ;
    USE SIGNAL ;
    PORT
      LAYER M4 ;
        RECT  172.716 39.36 172.8 39.384 ;
    END
  END u[74]
  PIN u[75]
    DIRECTION INPUT ;
    USE SIGNAL ;
    PORT
      LAYER M4 ;
        RECT  172.716 39.84 172.8 39.864 ;
    END
  END u[75]
  PIN u[76]
    DIRECTION INPUT ;
    USE SIGNAL ;
    PORT
      LAYER M4 ;
        RECT  172.716 40.224 172.8 40.248 ;
    END
  END u[76]
  PIN u[77]
    DIRECTION INPUT ;
    USE SIGNAL ;
    PORT
      LAYER M4 ;
        RECT  172.716 40.704 172.8 40.728 ;
    END
  END u[77]
  PIN u[78]
    DIRECTION INPUT ;
    USE SIGNAL ;
    PORT
      LAYER M4 ;
        RECT  172.716 41.088 172.8 41.112 ;
    END
  END u[78]
  PIN u[79]
    DIRECTION INPUT ;
    USE SIGNAL ;
    PORT
      LAYER M4 ;
        RECT  172.716 41.568 172.8 41.592 ;
    END
  END u[79]
  PIN u[7]
    DIRECTION INPUT ;
    USE SIGNAL ;
    PORT
      LAYER M4 ;
        RECT  172.716 9.408 172.8 9.432 ;
    END
  END u[7]
  PIN u[80]
    DIRECTION INPUT ;
    USE SIGNAL ;
    PORT
      LAYER M4 ;
        RECT  172.716 42.048 172.8 42.072 ;
    END
  END u[80]
  PIN u[81]
    DIRECTION INPUT ;
    USE SIGNAL ;
    PORT
      LAYER M4 ;
        RECT  172.716 42.432 172.8 42.456 ;
    END
  END u[81]
  PIN u[82]
    DIRECTION INPUT ;
    USE SIGNAL ;
    PORT
      LAYER M4 ;
        RECT  172.716 42.912 172.8 42.936 ;
    END
  END u[82]
  PIN u[83]
    DIRECTION INPUT ;
    USE SIGNAL ;
    PORT
      LAYER M4 ;
        RECT  172.716 43.392 172.8 43.416 ;
    END
  END u[83]
  PIN u[84]
    DIRECTION INPUT ;
    USE SIGNAL ;
    PORT
      LAYER M4 ;
        RECT  172.716 43.776 172.8 43.8 ;
    END
  END u[84]
  PIN u[85]
    DIRECTION INPUT ;
    USE SIGNAL ;
    PORT
      LAYER M4 ;
        RECT  172.716 44.256 172.8 44.28 ;
    END
  END u[85]
  PIN u[86]
    DIRECTION INPUT ;
    USE SIGNAL ;
    PORT
      LAYER M4 ;
        RECT  172.716 44.736 172.8 44.76 ;
    END
  END u[86]
  PIN u[87]
    DIRECTION INPUT ;
    USE SIGNAL ;
    PORT
      LAYER M4 ;
        RECT  172.716 45.12 172.8 45.144 ;
    END
  END u[87]
  PIN u[88]
    DIRECTION INPUT ;
    USE SIGNAL ;
    PORT
      LAYER M4 ;
        RECT  172.716 45.6 172.8 45.624 ;
    END
  END u[88]
  PIN u[89]
    DIRECTION INPUT ;
    USE SIGNAL ;
    PORT
      LAYER M4 ;
        RECT  172.716 46.08 172.8 46.104 ;
    END
  END u[89]
  PIN u[8]
    DIRECTION INPUT ;
    USE SIGNAL ;
    PORT
      LAYER M4 ;
        RECT  172.716 9.888 172.8 9.912 ;
    END
  END u[8]
  PIN u[90]
    DIRECTION INPUT ;
    USE SIGNAL ;
    PORT
      LAYER M4 ;
        RECT  172.716 46.464 172.8 46.488 ;
    END
  END u[90]
  PIN u[91]
    DIRECTION INPUT ;
    USE SIGNAL ;
    PORT
      LAYER M4 ;
        RECT  172.716 46.944 172.8 46.968 ;
    END
  END u[91]
  PIN u[92]
    DIRECTION INPUT ;
    USE SIGNAL ;
    PORT
      LAYER M4 ;
        RECT  172.716 47.424 172.8 47.448 ;
    END
  END u[92]
  PIN u[93]
    DIRECTION INPUT ;
    USE SIGNAL ;
    PORT
      LAYER M4 ;
        RECT  172.716 47.808 172.8 47.832 ;
    END
  END u[93]
  PIN u[94]
    DIRECTION INPUT ;
    USE SIGNAL ;
    PORT
      LAYER M4 ;
        RECT  172.716 48.288 172.8 48.312 ;
    END
  END u[94]
  PIN u[95]
    DIRECTION INPUT ;
    USE SIGNAL ;
    PORT
      LAYER M4 ;
        RECT  172.716 48.672 172.8 48.696 ;
    END
  END u[95]
  PIN u[96]
    DIRECTION INPUT ;
    USE SIGNAL ;
    PORT
      LAYER M4 ;
        RECT  172.716 49.152 172.8 49.176 ;
    END
  END u[96]
  PIN u[97]
    DIRECTION INPUT ;
    USE SIGNAL ;
    PORT
      LAYER M4 ;
        RECT  172.716 49.632 172.8 49.656 ;
    END
  END u[97]
  PIN u[98]
    DIRECTION INPUT ;
    USE SIGNAL ;
    PORT
      LAYER M4 ;
        RECT  172.716 50.016 172.8 50.04 ;
    END
  END u[98]
  PIN u[99]
    DIRECTION INPUT ;
    USE SIGNAL ;
    PORT
      LAYER M4 ;
        RECT  172.716 50.496 172.8 50.52 ;
    END
  END u[99]
  PIN u[9]
    DIRECTION INPUT ;
    USE SIGNAL ;
    PORT
      LAYER M4 ;
        RECT  172.716 10.368 172.8 10.392 ;
    END
  END u[9]
  PIN u_i[0]
    DIRECTION INPUT ;
    USE SIGNAL ;
    PORT
      LAYER M4 ;
        RECT  172.716 4.992 172.8 5.016 ;
    END
  END u_i[0]
  PIN u_i[1]
    DIRECTION INPUT ;
    USE SIGNAL ;
    PORT
      LAYER M4 ;
        RECT  172.716 5.376 172.8 5.4 ;
    END
  END u_i[1]
  PIN u_i[2]
    DIRECTION INPUT ;
    USE SIGNAL ;
    PORT
      LAYER M4 ;
        RECT  172.716 5.856 172.8 5.88 ;
    END
  END u_i[2]
  PIN u_v
    DIRECTION INPUT ;
    USE SIGNAL ;
    PORT
      LAYER M4 ;
        RECT  172.716 4.512 172.8 4.536 ;
    END
  END u_v
  PIN um_b
    DIRECTION INPUT ;
    USE SIGNAL ;
    PORT
      LAYER M4 ;
        RECT  172.716 121.44 172.8 121.464 ;
    END
  END um_b
  PIN um_i[0]
    DIRECTION INPUT ;
    USE SIGNAL ;
    PORT
      LAYER M4 ;
        RECT  172.716 121.92 172.8 121.944 ;
    END
  END um_i[0]
  PIN um_i[1]
    DIRECTION INPUT ;
    USE SIGNAL ;
    PORT
      LAYER M4 ;
        RECT  172.716 122.4 172.8 122.424 ;
    END
  END um_i[1]
  PIN um_i[2]
    DIRECTION INPUT ;
    USE SIGNAL ;
    PORT
      LAYER M4 ;
        RECT  172.716 122.784 172.8 122.808 ;
    END
  END um_i[2]
  PIN um_i[3]
    DIRECTION INPUT ;
    USE SIGNAL ;
    PORT
      LAYER M4 ;
        RECT  172.716 123.264 172.8 123.288 ;
    END
  END um_i[3]
  PIN um_i[4]
    DIRECTION INPUT ;
    USE SIGNAL ;
    PORT
      LAYER M4 ;
        RECT  172.716 123.744 172.8 123.768 ;
    END
  END um_i[4]
  PIN um_i[5]
    DIRECTION INPUT ;
    USE SIGNAL ;
    PORT
      LAYER M4 ;
        RECT  172.716 124.128 172.8 124.152 ;
    END
  END um_i[5]
  PIN um_i[6]
    DIRECTION INPUT ;
    USE SIGNAL ;
    PORT
      LAYER M4 ;
        RECT  172.716 124.608 172.8 124.632 ;
    END
  END um_i[6]
  PIN um_i[7]
    DIRECTION INPUT ;
    USE SIGNAL ;
    PORT
      LAYER M4 ;
        RECT  172.716 125.088 172.8 125.112 ;
    END
  END um_i[7]
  PIN um_q
    DIRECTION INPUT ;
    USE SIGNAL ;
    PORT
      LAYER M4 ;
        RECT  172.716 121.056 172.8 121.08 ;
    END
  END um_q
  PIN um_v
    DIRECTION INPUT ;
    USE SIGNAL ;
    PORT
      LAYER M4 ;
        RECT  172.716 120.576 172.8 120.6 ;
    END
  END um_v
  PIN xf[0]
    DIRECTION OUTPUT ;
    USE SIGNAL ;
    PORT
      LAYER M5 ;
        RECT  17.184 129.516 17.208 129.6 ;
    END
  END xf[0]
  PIN xf[100]
    DIRECTION OUTPUT ;
    USE SIGNAL ;
    PORT
      LAYER M5 ;
        RECT  72.096 129.516 72.12 129.6 ;
    END
  END xf[100]
  PIN xf[101]
    DIRECTION OUTPUT ;
    USE SIGNAL ;
    PORT
      LAYER M3 ;
        RECT  72.648 129.562 72.666 129.6 ;
    END
  END xf[101]
  PIN xf[102]
    DIRECTION OUTPUT ;
    USE SIGNAL ;
    PORT
      LAYER M5 ;
        RECT  73.248 129.516 73.272 129.6 ;
    END
  END xf[102]
  PIN xf[103]
    DIRECTION OUTPUT ;
    USE SIGNAL ;
    PORT
      LAYER M3 ;
        RECT  73.728 129.562 73.746 129.6 ;
    END
  END xf[103]
  PIN xf[104]
    DIRECTION OUTPUT ;
    USE SIGNAL ;
    PORT
      LAYER M5 ;
        RECT  74.304 129.516 74.328 129.6 ;
    END
  END xf[104]
  PIN xf[105]
    DIRECTION OUTPUT ;
    USE SIGNAL ;
    PORT
      LAYER M3 ;
        RECT  74.88 129.562 74.898 129.6 ;
    END
  END xf[105]
  PIN xf[106]
    DIRECTION OUTPUT ;
    USE SIGNAL ;
    PORT
      LAYER M5 ;
        RECT  75.36 129.516 75.384 129.6 ;
    END
  END xf[106]
  PIN xf[107]
    DIRECTION OUTPUT ;
    USE SIGNAL ;
    PORT
      LAYER M3 ;
        RECT  75.96 129.562 75.978 129.6 ;
    END
  END xf[107]
  PIN xf[108]
    DIRECTION OUTPUT ;
    USE SIGNAL ;
    PORT
      LAYER M5 ;
        RECT  76.512 129.516 76.536 129.6 ;
    END
  END xf[108]
  PIN xf[109]
    DIRECTION OUTPUT ;
    USE SIGNAL ;
    PORT
      LAYER M3 ;
        RECT  77.04 129.562 77.058 129.6 ;
    END
  END xf[109]
  PIN xf[10]
    DIRECTION OUTPUT ;
    USE SIGNAL ;
    PORT
      LAYER M5 ;
        RECT  22.656 129.516 22.68 129.6 ;
    END
  END xf[10]
  PIN xf[110]
    DIRECTION OUTPUT ;
    USE SIGNAL ;
    PORT
      LAYER M5 ;
        RECT  77.568 129.516 77.592 129.6 ;
    END
  END xf[110]
  PIN xf[111]
    DIRECTION OUTPUT ;
    USE SIGNAL ;
    PORT
      LAYER M3 ;
        RECT  78.12 129.562 78.138 129.6 ;
    END
  END xf[111]
  PIN xf[112]
    DIRECTION OUTPUT ;
    USE SIGNAL ;
    PORT
      LAYER M5 ;
        RECT  78.72 129.516 78.744 129.6 ;
    END
  END xf[112]
  PIN xf[113]
    DIRECTION OUTPUT ;
    USE SIGNAL ;
    PORT
      LAYER M3 ;
        RECT  79.272 129.562 79.29 129.6 ;
    END
  END xf[113]
  PIN xf[114]
    DIRECTION OUTPUT ;
    USE SIGNAL ;
    PORT
      LAYER M5 ;
        RECT  79.776 129.516 79.8 129.6 ;
    END
  END xf[114]
  PIN xf[115]
    DIRECTION OUTPUT ;
    USE SIGNAL ;
    PORT
      LAYER M3 ;
        RECT  80.352 129.562 80.37 129.6 ;
    END
  END xf[115]
  PIN xf[116]
    DIRECTION OUTPUT ;
    USE SIGNAL ;
    PORT
      LAYER M5 ;
        RECT  80.928 129.516 80.952 129.6 ;
    END
  END xf[116]
  PIN xf[117]
    DIRECTION OUTPUT ;
    USE SIGNAL ;
    PORT
      LAYER M3 ;
        RECT  81.432 129.562 81.45 129.6 ;
    END
  END xf[117]
  PIN xf[118]
    DIRECTION OUTPUT ;
    USE SIGNAL ;
    PORT
      LAYER M5 ;
        RECT  81.984 129.516 82.008 129.6 ;
    END
  END xf[118]
  PIN xf[119]
    DIRECTION OUTPUT ;
    USE SIGNAL ;
    PORT
      LAYER M3 ;
        RECT  82.512 129.562 82.53 129.6 ;
    END
  END xf[119]
  PIN xf[11]
    DIRECTION OUTPUT ;
    USE SIGNAL ;
    PORT
      LAYER M3 ;
        RECT  23.256 129.562 23.274 129.6 ;
    END
  END xf[11]
  PIN xf[120]
    DIRECTION OUTPUT ;
    USE SIGNAL ;
    PORT
      LAYER M5 ;
        RECT  83.136 129.516 83.16 129.6 ;
    END
  END xf[120]
  PIN xf[121]
    DIRECTION OUTPUT ;
    USE SIGNAL ;
    PORT
      LAYER M3 ;
        RECT  83.664 129.562 83.682 129.6 ;
    END
  END xf[121]
  PIN xf[122]
    DIRECTION OUTPUT ;
    USE SIGNAL ;
    PORT
      LAYER M5 ;
        RECT  84.192 129.516 84.216 129.6 ;
    END
  END xf[122]
  PIN xf[123]
    DIRECTION OUTPUT ;
    USE SIGNAL ;
    PORT
      LAYER M3 ;
        RECT  84.744 129.562 84.762 129.6 ;
    END
  END xf[123]
  PIN xf[124]
    DIRECTION OUTPUT ;
    USE SIGNAL ;
    PORT
      LAYER M5 ;
        RECT  85.248 129.516 85.272 129.6 ;
    END
  END xf[124]
  PIN xf[125]
    DIRECTION OUTPUT ;
    USE SIGNAL ;
    PORT
      LAYER M3 ;
        RECT  85.824 129.562 85.842 129.6 ;
    END
  END xf[125]
  PIN xf[126]
    DIRECTION OUTPUT ;
    USE SIGNAL ;
    PORT
      LAYER M5 ;
        RECT  86.4 129.516 86.424 129.6 ;
    END
  END xf[126]
  PIN xf[127]
    DIRECTION OUTPUT ;
    USE SIGNAL ;
    PORT
      LAYER M3 ;
        RECT  86.976 129.562 86.994 129.6 ;
    END
  END xf[127]
  PIN xf[128]
    DIRECTION OUTPUT ;
    USE SIGNAL ;
    PORT
      LAYER M5 ;
        RECT  87.456 129.516 87.48 129.6 ;
    END
  END xf[128]
  PIN xf[129]
    DIRECTION OUTPUT ;
    USE SIGNAL ;
    PORT
      LAYER M3 ;
        RECT  88.056 129.562 88.074 129.6 ;
    END
  END xf[129]
  PIN xf[12]
    DIRECTION OUTPUT ;
    USE SIGNAL ;
    PORT
      LAYER M5 ;
        RECT  23.808 129.516 23.832 129.6 ;
    END
  END xf[12]
  PIN xf[130]
    DIRECTION OUTPUT ;
    USE SIGNAL ;
    PORT
      LAYER M5 ;
        RECT  88.608 129.516 88.632 129.6 ;
    END
  END xf[130]
  PIN xf[131]
    DIRECTION OUTPUT ;
    USE SIGNAL ;
    PORT
      LAYER M3 ;
        RECT  89.136 129.562 89.154 129.6 ;
    END
  END xf[131]
  PIN xf[132]
    DIRECTION OUTPUT ;
    USE SIGNAL ;
    PORT
      LAYER M5 ;
        RECT  89.664 129.516 89.688 129.6 ;
    END
  END xf[132]
  PIN xf[133]
    DIRECTION OUTPUT ;
    USE SIGNAL ;
    PORT
      LAYER M3 ;
        RECT  90.216 129.562 90.234 129.6 ;
    END
  END xf[133]
  PIN xf[134]
    DIRECTION OUTPUT ;
    USE SIGNAL ;
    PORT
      LAYER M5 ;
        RECT  90.816 129.516 90.84 129.6 ;
    END
  END xf[134]
  PIN xf[135]
    DIRECTION OUTPUT ;
    USE SIGNAL ;
    PORT
      LAYER M3 ;
        RECT  91.368 129.562 91.386 129.6 ;
    END
  END xf[135]
  PIN xf[136]
    DIRECTION OUTPUT ;
    USE SIGNAL ;
    PORT
      LAYER M5 ;
        RECT  91.872 129.516 91.896 129.6 ;
    END
  END xf[136]
  PIN xf[137]
    DIRECTION OUTPUT ;
    USE SIGNAL ;
    PORT
      LAYER M3 ;
        RECT  92.448 129.562 92.466 129.6 ;
    END
  END xf[137]
  PIN xf[138]
    DIRECTION OUTPUT ;
    USE SIGNAL ;
    PORT
      LAYER M5 ;
        RECT  93.024 129.516 93.048 129.6 ;
    END
  END xf[138]
  PIN xf[139]
    DIRECTION OUTPUT ;
    USE SIGNAL ;
    PORT
      LAYER M3 ;
        RECT  93.528 129.562 93.546 129.6 ;
    END
  END xf[139]
  PIN xf[13]
    DIRECTION OUTPUT ;
    USE SIGNAL ;
    PORT
      LAYER M3 ;
        RECT  24.336 129.562 24.354 129.6 ;
    END
  END xf[13]
  PIN xf[140]
    DIRECTION OUTPUT ;
    USE SIGNAL ;
    PORT
      LAYER M5 ;
        RECT  94.08 129.516 94.104 129.6 ;
    END
  END xf[140]
  PIN xf[141]
    DIRECTION OUTPUT ;
    USE SIGNAL ;
    PORT
      LAYER M3 ;
        RECT  94.608 129.562 94.626 129.6 ;
    END
  END xf[141]
  PIN xf[142]
    DIRECTION OUTPUT ;
    USE SIGNAL ;
    PORT
      LAYER M5 ;
        RECT  95.136 129.516 95.16 129.6 ;
    END
  END xf[142]
  PIN xf[143]
    DIRECTION OUTPUT ;
    USE SIGNAL ;
    PORT
      LAYER M3 ;
        RECT  95.76 129.562 95.778 129.6 ;
    END
  END xf[143]
  PIN xf[144]
    DIRECTION OUTPUT ;
    USE SIGNAL ;
    PORT
      LAYER M5 ;
        RECT  96.288 129.516 96.312 129.6 ;
    END
  END xf[144]
  PIN xf[145]
    DIRECTION OUTPUT ;
    USE SIGNAL ;
    PORT
      LAYER M3 ;
        RECT  96.84 129.562 96.858 129.6 ;
    END
  END xf[145]
  PIN xf[146]
    DIRECTION OUTPUT ;
    USE SIGNAL ;
    PORT
      LAYER M5 ;
        RECT  97.344 129.516 97.368 129.6 ;
    END
  END xf[146]
  PIN xf[147]
    DIRECTION OUTPUT ;
    USE SIGNAL ;
    PORT
      LAYER M3 ;
        RECT  97.92 129.562 97.938 129.6 ;
    END
  END xf[147]
  PIN xf[148]
    DIRECTION OUTPUT ;
    USE SIGNAL ;
    PORT
      LAYER M5 ;
        RECT  98.496 129.516 98.52 129.6 ;
    END
  END xf[148]
  PIN xf[149]
    DIRECTION OUTPUT ;
    USE SIGNAL ;
    PORT
      LAYER M3 ;
        RECT  99 129.562 99.018 129.6 ;
    END
  END xf[149]
  PIN xf[14]
    DIRECTION OUTPUT ;
    USE SIGNAL ;
    PORT
      LAYER M5 ;
        RECT  24.864 129.516 24.888 129.6 ;
    END
  END xf[14]
  PIN xf[150]
    DIRECTION OUTPUT ;
    USE SIGNAL ;
    PORT
      LAYER M5 ;
        RECT  99.552 129.516 99.576 129.6 ;
    END
  END xf[150]
  PIN xf[151]
    DIRECTION OUTPUT ;
    USE SIGNAL ;
    PORT
      LAYER M3 ;
        RECT  100.152 129.562 100.17 129.6 ;
    END
  END xf[151]
  PIN xf[152]
    DIRECTION OUTPUT ;
    USE SIGNAL ;
    PORT
      LAYER M5 ;
        RECT  100.704 129.516 100.728 129.6 ;
    END
  END xf[152]
  PIN xf[153]
    DIRECTION OUTPUT ;
    USE SIGNAL ;
    PORT
      LAYER M3 ;
        RECT  101.232 129.562 101.25 129.6 ;
    END
  END xf[153]
  PIN xf[154]
    DIRECTION OUTPUT ;
    USE SIGNAL ;
    PORT
      LAYER M5 ;
        RECT  101.76 129.516 101.784 129.6 ;
    END
  END xf[154]
  PIN xf[155]
    DIRECTION OUTPUT ;
    USE SIGNAL ;
    PORT
      LAYER M3 ;
        RECT  102.312 129.562 102.33 129.6 ;
    END
  END xf[155]
  PIN xf[156]
    DIRECTION OUTPUT ;
    USE SIGNAL ;
    PORT
      LAYER M5 ;
        RECT  102.816 129.516 102.84 129.6 ;
    END
  END xf[156]
  PIN xf[157]
    DIRECTION OUTPUT ;
    USE SIGNAL ;
    PORT
      LAYER M3 ;
        RECT  103.392 129.562 103.41 129.6 ;
    END
  END xf[157]
  PIN xf[158]
    DIRECTION OUTPUT ;
    USE SIGNAL ;
    PORT
      LAYER M5 ;
        RECT  103.968 129.516 103.992 129.6 ;
    END
  END xf[158]
  PIN xf[159]
    DIRECTION OUTPUT ;
    USE SIGNAL ;
    PORT
      LAYER M3 ;
        RECT  104.544 129.562 104.562 129.6 ;
    END
  END xf[159]
  PIN xf[15]
    DIRECTION OUTPUT ;
    USE SIGNAL ;
    PORT
      LAYER M3 ;
        RECT  25.416 129.562 25.434 129.6 ;
    END
  END xf[15]
  PIN xf[160]
    DIRECTION OUTPUT ;
    USE SIGNAL ;
    PORT
      LAYER M5 ;
        RECT  105.024 129.516 105.048 129.6 ;
    END
  END xf[160]
  PIN xf[161]
    DIRECTION OUTPUT ;
    USE SIGNAL ;
    PORT
      LAYER M3 ;
        RECT  105.624 129.562 105.642 129.6 ;
    END
  END xf[161]
  PIN xf[162]
    DIRECTION OUTPUT ;
    USE SIGNAL ;
    PORT
      LAYER M5 ;
        RECT  106.176 129.516 106.2 129.6 ;
    END
  END xf[162]
  PIN xf[163]
    DIRECTION OUTPUT ;
    USE SIGNAL ;
    PORT
      LAYER M3 ;
        RECT  106.704 129.562 106.722 129.6 ;
    END
  END xf[163]
  PIN xf[164]
    DIRECTION OUTPUT ;
    USE SIGNAL ;
    PORT
      LAYER M5 ;
        RECT  107.232 129.516 107.256 129.6 ;
    END
  END xf[164]
  PIN xf[165]
    DIRECTION OUTPUT ;
    USE SIGNAL ;
    PORT
      LAYER M3 ;
        RECT  107.784 129.562 107.802 129.6 ;
    END
  END xf[165]
  PIN xf[166]
    DIRECTION OUTPUT ;
    USE SIGNAL ;
    PORT
      LAYER M5 ;
        RECT  108.384 129.516 108.408 129.6 ;
    END
  END xf[166]
  PIN xf[167]
    DIRECTION OUTPUT ;
    USE SIGNAL ;
    PORT
      LAYER M3 ;
        RECT  108.936 129.562 108.954 129.6 ;
    END
  END xf[167]
  PIN xf[168]
    DIRECTION OUTPUT ;
    USE SIGNAL ;
    PORT
      LAYER M5 ;
        RECT  109.44 129.516 109.464 129.6 ;
    END
  END xf[168]
  PIN xf[169]
    DIRECTION OUTPUT ;
    USE SIGNAL ;
    PORT
      LAYER M3 ;
        RECT  110.016 129.562 110.034 129.6 ;
    END
  END xf[169]
  PIN xf[16]
    DIRECTION OUTPUT ;
    USE SIGNAL ;
    PORT
      LAYER M5 ;
        RECT  26.016 129.516 26.04 129.6 ;
    END
  END xf[16]
  PIN xf[170]
    DIRECTION OUTPUT ;
    USE SIGNAL ;
    PORT
      LAYER M5 ;
        RECT  110.592 129.516 110.616 129.6 ;
    END
  END xf[170]
  PIN xf[171]
    DIRECTION OUTPUT ;
    USE SIGNAL ;
    PORT
      LAYER M3 ;
        RECT  111.096 129.562 111.114 129.6 ;
    END
  END xf[171]
  PIN xf[172]
    DIRECTION OUTPUT ;
    USE SIGNAL ;
    PORT
      LAYER M5 ;
        RECT  111.648 129.516 111.672 129.6 ;
    END
  END xf[172]
  PIN xf[173]
    DIRECTION OUTPUT ;
    USE SIGNAL ;
    PORT
      LAYER M3 ;
        RECT  112.176 129.562 112.194 129.6 ;
    END
  END xf[173]
  PIN xf[174]
    DIRECTION OUTPUT ;
    USE SIGNAL ;
    PORT
      LAYER M5 ;
        RECT  112.704 129.516 112.728 129.6 ;
    END
  END xf[174]
  PIN xf[175]
    DIRECTION OUTPUT ;
    USE SIGNAL ;
    PORT
      LAYER M3 ;
        RECT  113.328 129.562 113.346 129.6 ;
    END
  END xf[175]
  PIN xf[176]
    DIRECTION OUTPUT ;
    USE SIGNAL ;
    PORT
      LAYER M5 ;
        RECT  113.856 129.516 113.88 129.6 ;
    END
  END xf[176]
  PIN xf[177]
    DIRECTION OUTPUT ;
    USE SIGNAL ;
    PORT
      LAYER M3 ;
        RECT  114.408 129.562 114.426 129.6 ;
    END
  END xf[177]
  PIN xf[178]
    DIRECTION OUTPUT ;
    USE SIGNAL ;
    PORT
      LAYER M5 ;
        RECT  114.912 129.516 114.936 129.6 ;
    END
  END xf[178]
  PIN xf[179]
    DIRECTION OUTPUT ;
    USE SIGNAL ;
    PORT
      LAYER M3 ;
        RECT  115.488 129.562 115.506 129.6 ;
    END
  END xf[179]
  PIN xf[17]
    DIRECTION OUTPUT ;
    USE SIGNAL ;
    PORT
      LAYER M3 ;
        RECT  26.568 129.562 26.586 129.6 ;
    END
  END xf[17]
  PIN xf[180]
    DIRECTION OUTPUT ;
    USE SIGNAL ;
    PORT
      LAYER M5 ;
        RECT  116.064 129.516 116.088 129.6 ;
    END
  END xf[180]
  PIN xf[181]
    DIRECTION OUTPUT ;
    USE SIGNAL ;
    PORT
      LAYER M3 ;
        RECT  116.568 129.562 116.586 129.6 ;
    END
  END xf[181]
  PIN xf[182]
    DIRECTION OUTPUT ;
    USE SIGNAL ;
    PORT
      LAYER M5 ;
        RECT  117.12 129.516 117.144 129.6 ;
    END
  END xf[182]
  PIN xf[183]
    DIRECTION OUTPUT ;
    USE SIGNAL ;
    PORT
      LAYER M3 ;
        RECT  117.72 129.562 117.738 129.6 ;
    END
  END xf[183]
  PIN xf[184]
    DIRECTION OUTPUT ;
    USE SIGNAL ;
    PORT
      LAYER M5 ;
        RECT  118.272 129.516 118.296 129.6 ;
    END
  END xf[184]
  PIN xf[185]
    DIRECTION OUTPUT ;
    USE SIGNAL ;
    PORT
      LAYER M3 ;
        RECT  118.8 129.562 118.818 129.6 ;
    END
  END xf[185]
  PIN xf[186]
    DIRECTION OUTPUT ;
    USE SIGNAL ;
    PORT
      LAYER M5 ;
        RECT  119.328 129.516 119.352 129.6 ;
    END
  END xf[186]
  PIN xf[187]
    DIRECTION OUTPUT ;
    USE SIGNAL ;
    PORT
      LAYER M3 ;
        RECT  119.88 129.562 119.898 129.6 ;
    END
  END xf[187]
  PIN xf[188]
    DIRECTION OUTPUT ;
    USE SIGNAL ;
    PORT
      LAYER M5 ;
        RECT  120.384 129.516 120.408 129.6 ;
    END
  END xf[188]
  PIN xf[189]
    DIRECTION OUTPUT ;
    USE SIGNAL ;
    PORT
      LAYER M3 ;
        RECT  120.96 129.562 120.978 129.6 ;
    END
  END xf[189]
  PIN xf[18]
    DIRECTION OUTPUT ;
    USE SIGNAL ;
    PORT
      LAYER M5 ;
        RECT  27.072 129.516 27.096 129.6 ;
    END
  END xf[18]
  PIN xf[190]
    DIRECTION OUTPUT ;
    USE SIGNAL ;
    PORT
      LAYER M5 ;
        RECT  121.536 129.516 121.56 129.6 ;
    END
  END xf[190]
  PIN xf[191]
    DIRECTION OUTPUT ;
    USE SIGNAL ;
    PORT
      LAYER M3 ;
        RECT  122.112 129.562 122.13 129.6 ;
    END
  END xf[191]
  PIN xf[192]
    DIRECTION OUTPUT ;
    USE SIGNAL ;
    PORT
      LAYER M5 ;
        RECT  122.592 129.516 122.616 129.6 ;
    END
  END xf[192]
  PIN xf[193]
    DIRECTION OUTPUT ;
    USE SIGNAL ;
    PORT
      LAYER M3 ;
        RECT  123.192 129.562 123.21 129.6 ;
    END
  END xf[193]
  PIN xf[194]
    DIRECTION OUTPUT ;
    USE SIGNAL ;
    PORT
      LAYER M5 ;
        RECT  123.744 129.516 123.768 129.6 ;
    END
  END xf[194]
  PIN xf[195]
    DIRECTION OUTPUT ;
    USE SIGNAL ;
    PORT
      LAYER M3 ;
        RECT  124.272 129.562 124.29 129.6 ;
    END
  END xf[195]
  PIN xf[196]
    DIRECTION OUTPUT ;
    USE SIGNAL ;
    PORT
      LAYER M5 ;
        RECT  124.8 129.516 124.824 129.6 ;
    END
  END xf[196]
  PIN xf[197]
    DIRECTION OUTPUT ;
    USE SIGNAL ;
    PORT
      LAYER M3 ;
        RECT  125.352 129.562 125.37 129.6 ;
    END
  END xf[197]
  PIN xf[198]
    DIRECTION OUTPUT ;
    USE SIGNAL ;
    PORT
      LAYER M5 ;
        RECT  125.952 129.516 125.976 129.6 ;
    END
  END xf[198]
  PIN xf[199]
    DIRECTION OUTPUT ;
    USE SIGNAL ;
    PORT
      LAYER M3 ;
        RECT  126.504 129.562 126.522 129.6 ;
    END
  END xf[199]
  PIN xf[19]
    DIRECTION OUTPUT ;
    USE SIGNAL ;
    PORT
      LAYER M3 ;
        RECT  27.648 129.562 27.666 129.6 ;
    END
  END xf[19]
  PIN xf[1]
    DIRECTION OUTPUT ;
    USE SIGNAL ;
    PORT
      LAYER M3 ;
        RECT  17.784 129.562 17.802 129.6 ;
    END
  END xf[1]
  PIN xf[200]
    DIRECTION OUTPUT ;
    USE SIGNAL ;
    PORT
      LAYER M5 ;
        RECT  127.008 129.516 127.032 129.6 ;
    END
  END xf[200]
  PIN xf[201]
    DIRECTION OUTPUT ;
    USE SIGNAL ;
    PORT
      LAYER M3 ;
        RECT  127.584 129.562 127.602 129.6 ;
    END
  END xf[201]
  PIN xf[202]
    DIRECTION OUTPUT ;
    USE SIGNAL ;
    PORT
      LAYER M5 ;
        RECT  128.16 129.516 128.184 129.6 ;
    END
  END xf[202]
  PIN xf[203]
    DIRECTION OUTPUT ;
    USE SIGNAL ;
    PORT
      LAYER M3 ;
        RECT  128.664 129.562 128.682 129.6 ;
    END
  END xf[203]
  PIN xf[204]
    DIRECTION OUTPUT ;
    USE SIGNAL ;
    PORT
      LAYER M5 ;
        RECT  129.216 129.516 129.24 129.6 ;
    END
  END xf[204]
  PIN xf[205]
    DIRECTION OUTPUT ;
    USE SIGNAL ;
    PORT
      LAYER M3 ;
        RECT  129.744 129.562 129.762 129.6 ;
    END
  END xf[205]
  PIN xf[206]
    DIRECTION OUTPUT ;
    USE SIGNAL ;
    PORT
      LAYER M5 ;
        RECT  130.272 129.516 130.296 129.6 ;
    END
  END xf[206]
  PIN xf[207]
    DIRECTION OUTPUT ;
    USE SIGNAL ;
    PORT
      LAYER M3 ;
        RECT  130.896 129.562 130.914 129.6 ;
    END
  END xf[207]
  PIN xf[208]
    DIRECTION OUTPUT ;
    USE SIGNAL ;
    PORT
      LAYER M5 ;
        RECT  131.424 129.516 131.448 129.6 ;
    END
  END xf[208]
  PIN xf[209]
    DIRECTION OUTPUT ;
    USE SIGNAL ;
    PORT
      LAYER M3 ;
        RECT  131.976 129.562 131.994 129.6 ;
    END
  END xf[209]
  PIN xf[20]
    DIRECTION OUTPUT ;
    USE SIGNAL ;
    PORT
      LAYER M5 ;
        RECT  28.224 129.516 28.248 129.6 ;
    END
  END xf[20]
  PIN xf[210]
    DIRECTION OUTPUT ;
    USE SIGNAL ;
    PORT
      LAYER M5 ;
        RECT  132.48 129.516 132.504 129.6 ;
    END
  END xf[210]
  PIN xf[211]
    DIRECTION OUTPUT ;
    USE SIGNAL ;
    PORT
      LAYER M3 ;
        RECT  133.056 129.562 133.074 129.6 ;
    END
  END xf[211]
  PIN xf[212]
    DIRECTION OUTPUT ;
    USE SIGNAL ;
    PORT
      LAYER M5 ;
        RECT  133.632 129.516 133.656 129.6 ;
    END
  END xf[212]
  PIN xf[213]
    DIRECTION OUTPUT ;
    USE SIGNAL ;
    PORT
      LAYER M3 ;
        RECT  134.136 129.562 134.154 129.6 ;
    END
  END xf[213]
  PIN xf[214]
    DIRECTION OUTPUT ;
    USE SIGNAL ;
    PORT
      LAYER M5 ;
        RECT  134.688 129.516 134.712 129.6 ;
    END
  END xf[214]
  PIN xf[215]
    DIRECTION OUTPUT ;
    USE SIGNAL ;
    PORT
      LAYER M3 ;
        RECT  135.288 129.562 135.306 129.6 ;
    END
  END xf[215]
  PIN xf[216]
    DIRECTION OUTPUT ;
    USE SIGNAL ;
    PORT
      LAYER M5 ;
        RECT  135.84 129.516 135.864 129.6 ;
    END
  END xf[216]
  PIN xf[217]
    DIRECTION OUTPUT ;
    USE SIGNAL ;
    PORT
      LAYER M3 ;
        RECT  136.368 129.562 136.386 129.6 ;
    END
  END xf[217]
  PIN xf[218]
    DIRECTION OUTPUT ;
    USE SIGNAL ;
    PORT
      LAYER M5 ;
        RECT  136.896 129.516 136.92 129.6 ;
    END
  END xf[218]
  PIN xf[219]
    DIRECTION OUTPUT ;
    USE SIGNAL ;
    PORT
      LAYER M3 ;
        RECT  137.448 129.562 137.466 129.6 ;
    END
  END xf[219]
  PIN xf[21]
    DIRECTION OUTPUT ;
    USE SIGNAL ;
    PORT
      LAYER M3 ;
        RECT  28.728 129.562 28.746 129.6 ;
    END
  END xf[21]
  PIN xf[220]
    DIRECTION OUTPUT ;
    USE SIGNAL ;
    PORT
      LAYER M5 ;
        RECT  137.952 129.516 137.976 129.6 ;
    END
  END xf[220]
  PIN xf[221]
    DIRECTION OUTPUT ;
    USE SIGNAL ;
    PORT
      LAYER M3 ;
        RECT  138.528 129.562 138.546 129.6 ;
    END
  END xf[221]
  PIN xf[222]
    DIRECTION OUTPUT ;
    USE SIGNAL ;
    PORT
      LAYER M5 ;
        RECT  139.104 129.516 139.128 129.6 ;
    END
  END xf[222]
  PIN xf[223]
    DIRECTION OUTPUT ;
    USE SIGNAL ;
    PORT
      LAYER M3 ;
        RECT  139.68 129.562 139.698 129.6 ;
    END
  END xf[223]
  PIN xf[224]
    DIRECTION OUTPUT ;
    USE SIGNAL ;
    PORT
      LAYER M5 ;
        RECT  140.16 129.516 140.184 129.6 ;
    END
  END xf[224]
  PIN xf[225]
    DIRECTION OUTPUT ;
    USE SIGNAL ;
    PORT
      LAYER M3 ;
        RECT  140.76 129.562 140.778 129.6 ;
    END
  END xf[225]
  PIN xf[226]
    DIRECTION OUTPUT ;
    USE SIGNAL ;
    PORT
      LAYER M5 ;
        RECT  141.312 129.516 141.336 129.6 ;
    END
  END xf[226]
  PIN xf[227]
    DIRECTION OUTPUT ;
    USE SIGNAL ;
    PORT
      LAYER M3 ;
        RECT  141.84 129.562 141.858 129.6 ;
    END
  END xf[227]
  PIN xf[228]
    DIRECTION OUTPUT ;
    USE SIGNAL ;
    PORT
      LAYER M5 ;
        RECT  142.368 129.516 142.392 129.6 ;
    END
  END xf[228]
  PIN xf[229]
    DIRECTION OUTPUT ;
    USE SIGNAL ;
    PORT
      LAYER M3 ;
        RECT  142.92 129.562 142.938 129.6 ;
    END
  END xf[229]
  PIN xf[22]
    DIRECTION OUTPUT ;
    USE SIGNAL ;
    PORT
      LAYER M5 ;
        RECT  29.28 129.516 29.304 129.6 ;
    END
  END xf[22]
  PIN xf[230]
    DIRECTION OUTPUT ;
    USE SIGNAL ;
    PORT
      LAYER M5 ;
        RECT  143.52 129.516 143.544 129.6 ;
    END
  END xf[230]
  PIN xf[231]
    DIRECTION OUTPUT ;
    USE SIGNAL ;
    PORT
      LAYER M3 ;
        RECT  144.072 129.562 144.09 129.6 ;
    END
  END xf[231]
  PIN xf[232]
    DIRECTION OUTPUT ;
    USE SIGNAL ;
    PORT
      LAYER M5 ;
        RECT  144.576 129.516 144.6 129.6 ;
    END
  END xf[232]
  PIN xf[233]
    DIRECTION OUTPUT ;
    USE SIGNAL ;
    PORT
      LAYER M3 ;
        RECT  145.152 129.562 145.17 129.6 ;
    END
  END xf[233]
  PIN xf[234]
    DIRECTION OUTPUT ;
    USE SIGNAL ;
    PORT
      LAYER M5 ;
        RECT  145.728 129.516 145.752 129.6 ;
    END
  END xf[234]
  PIN xf[235]
    DIRECTION OUTPUT ;
    USE SIGNAL ;
    PORT
      LAYER M3 ;
        RECT  146.232 129.562 146.25 129.6 ;
    END
  END xf[235]
  PIN xf[236]
    DIRECTION OUTPUT ;
    USE SIGNAL ;
    PORT
      LAYER M5 ;
        RECT  146.784 129.516 146.808 129.6 ;
    END
  END xf[236]
  PIN xf[237]
    DIRECTION OUTPUT ;
    USE SIGNAL ;
    PORT
      LAYER M3 ;
        RECT  147.312 129.562 147.33 129.6 ;
    END
  END xf[237]
  PIN xf[238]
    DIRECTION OUTPUT ;
    USE SIGNAL ;
    PORT
      LAYER M5 ;
        RECT  147.84 129.516 147.864 129.6 ;
    END
  END xf[238]
  PIN xf[239]
    DIRECTION OUTPUT ;
    USE SIGNAL ;
    PORT
      LAYER M3 ;
        RECT  148.464 129.562 148.482 129.6 ;
    END
  END xf[239]
  PIN xf[23]
    DIRECTION OUTPUT ;
    USE SIGNAL ;
    PORT
      LAYER M3 ;
        RECT  29.808 129.562 29.826 129.6 ;
    END
  END xf[23]
  PIN xf[240]
    DIRECTION OUTPUT ;
    USE SIGNAL ;
    PORT
      LAYER M5 ;
        RECT  148.992 129.516 149.016 129.6 ;
    END
  END xf[240]
  PIN xf[241]
    DIRECTION OUTPUT ;
    USE SIGNAL ;
    PORT
      LAYER M3 ;
        RECT  149.544 129.562 149.562 129.6 ;
    END
  END xf[241]
  PIN xf[242]
    DIRECTION OUTPUT ;
    USE SIGNAL ;
    PORT
      LAYER M5 ;
        RECT  150.048 129.516 150.072 129.6 ;
    END
  END xf[242]
  PIN xf[243]
    DIRECTION OUTPUT ;
    USE SIGNAL ;
    PORT
      LAYER M3 ;
        RECT  150.624 129.562 150.642 129.6 ;
    END
  END xf[243]
  PIN xf[244]
    DIRECTION OUTPUT ;
    USE SIGNAL ;
    PORT
      LAYER M5 ;
        RECT  151.2 129.516 151.224 129.6 ;
    END
  END xf[244]
  PIN xf[245]
    DIRECTION OUTPUT ;
    USE SIGNAL ;
    PORT
      LAYER M3 ;
        RECT  151.704 129.562 151.722 129.6 ;
    END
  END xf[245]
  PIN xf[246]
    DIRECTION OUTPUT ;
    USE SIGNAL ;
    PORT
      LAYER M5 ;
        RECT  152.256 129.516 152.28 129.6 ;
    END
  END xf[246]
  PIN xf[247]
    DIRECTION OUTPUT ;
    USE SIGNAL ;
    PORT
      LAYER M3 ;
        RECT  152.856 129.562 152.874 129.6 ;
    END
  END xf[247]
  PIN xf[248]
    DIRECTION OUTPUT ;
    USE SIGNAL ;
    PORT
      LAYER M5 ;
        RECT  153.408 129.516 153.432 129.6 ;
    END
  END xf[248]
  PIN xf[249]
    DIRECTION OUTPUT ;
    USE SIGNAL ;
    PORT
      LAYER M3 ;
        RECT  153.936 129.562 153.954 129.6 ;
    END
  END xf[249]
  PIN xf[24]
    DIRECTION OUTPUT ;
    USE SIGNAL ;
    PORT
      LAYER M5 ;
        RECT  30.432 129.516 30.456 129.6 ;
    END
  END xf[24]
  PIN xf[250]
    DIRECTION OUTPUT ;
    USE SIGNAL ;
    PORT
      LAYER M5 ;
        RECT  154.464 129.516 154.488 129.6 ;
    END
  END xf[250]
  PIN xf[251]
    DIRECTION OUTPUT ;
    USE SIGNAL ;
    PORT
      LAYER M3 ;
        RECT  155.016 129.562 155.034 129.6 ;
    END
  END xf[251]
  PIN xf[252]
    DIRECTION OUTPUT ;
    USE SIGNAL ;
    PORT
      LAYER M5 ;
        RECT  155.52 129.516 155.544 129.6 ;
    END
  END xf[252]
  PIN xf[253]
    DIRECTION OUTPUT ;
    USE SIGNAL ;
    PORT
      LAYER M3 ;
        RECT  156.096 129.562 156.114 129.6 ;
    END
  END xf[253]
  PIN xf[254]
    DIRECTION OUTPUT ;
    USE SIGNAL ;
    PORT
      LAYER M5 ;
        RECT  156.672 129.516 156.696 129.6 ;
    END
  END xf[254]
  PIN xf[255]
    DIRECTION OUTPUT ;
    USE SIGNAL ;
    PORT
      LAYER M3 ;
        RECT  157.248 129.562 157.266 129.6 ;
    END
  END xf[255]
  PIN xf[256]
    DIRECTION OUTPUT ;
    USE SIGNAL ;
    PORT
      LAYER M5 ;
        RECT  157.728 129.516 157.752 129.6 ;
    END
  END xf[256]
  PIN xf[257]
    DIRECTION OUTPUT ;
    USE SIGNAL ;
    PORT
      LAYER M3 ;
        RECT  158.328 129.562 158.346 129.6 ;
    END
  END xf[257]
  PIN xf[258]
    DIRECTION OUTPUT ;
    USE SIGNAL ;
    PORT
      LAYER M5 ;
        RECT  158.88 129.516 158.904 129.6 ;
    END
  END xf[258]
  PIN xf[259]
    DIRECTION OUTPUT ;
    USE SIGNAL ;
    PORT
      LAYER M3 ;
        RECT  159.408 129.562 159.426 129.6 ;
    END
  END xf[259]
  PIN xf[25]
    DIRECTION OUTPUT ;
    USE SIGNAL ;
    PORT
      LAYER M3 ;
        RECT  30.96 129.562 30.978 129.6 ;
    END
  END xf[25]
  PIN xf[260]
    DIRECTION OUTPUT ;
    USE SIGNAL ;
    PORT
      LAYER M5 ;
        RECT  159.936 129.516 159.96 129.6 ;
    END
  END xf[260]
  PIN xf[261]
    DIRECTION OUTPUT ;
    USE SIGNAL ;
    PORT
      LAYER M3 ;
        RECT  160.488 129.562 160.506 129.6 ;
    END
  END xf[261]
  PIN xf[262]
    DIRECTION OUTPUT ;
    USE SIGNAL ;
    PORT
      LAYER M5 ;
        RECT  161.088 129.516 161.112 129.6 ;
    END
  END xf[262]
  PIN xf[263]
    DIRECTION OUTPUT ;
    USE SIGNAL ;
    PORT
      LAYER M3 ;
        RECT  161.64 129.562 161.658 129.6 ;
    END
  END xf[263]
  PIN xf[264]
    DIRECTION OUTPUT ;
    USE SIGNAL ;
    PORT
      LAYER M5 ;
        RECT  162.144 129.516 162.168 129.6 ;
    END
  END xf[264]
  PIN xf[265]
    DIRECTION OUTPUT ;
    USE SIGNAL ;
    PORT
      LAYER M3 ;
        RECT  162.72 129.562 162.738 129.6 ;
    END
  END xf[265]
  PIN xf[266]
    DIRECTION OUTPUT ;
    USE SIGNAL ;
    PORT
      LAYER M5 ;
        RECT  163.296 129.516 163.32 129.6 ;
    END
  END xf[266]
  PIN xf[267]
    DIRECTION OUTPUT ;
    USE SIGNAL ;
    PORT
      LAYER M3 ;
        RECT  163.8 129.562 163.818 129.6 ;
    END
  END xf[267]
  PIN xf[268]
    DIRECTION OUTPUT ;
    USE SIGNAL ;
    PORT
      LAYER M5 ;
        RECT  164.352 129.516 164.376 129.6 ;
    END
  END xf[268]
  PIN xf[269]
    DIRECTION OUTPUT ;
    USE SIGNAL ;
    PORT
      LAYER M3 ;
        RECT  164.88 129.562 164.898 129.6 ;
    END
  END xf[269]
  PIN xf[26]
    DIRECTION OUTPUT ;
    USE SIGNAL ;
    PORT
      LAYER M5 ;
        RECT  31.488 129.516 31.512 129.6 ;
    END
  END xf[26]
  PIN xf[270]
    DIRECTION OUTPUT ;
    USE SIGNAL ;
    PORT
      LAYER M5 ;
        RECT  165.408 129.516 165.432 129.6 ;
    END
  END xf[270]
  PIN xf[271]
    DIRECTION OUTPUT ;
    USE SIGNAL ;
    PORT
      LAYER M3 ;
        RECT  166.032 129.562 166.05 129.6 ;
    END
  END xf[271]
  PIN xf[272]
    DIRECTION OUTPUT ;
    USE SIGNAL ;
    PORT
      LAYER M5 ;
        RECT  166.56 129.516 166.584 129.6 ;
    END
  END xf[272]
  PIN xf[273]
    DIRECTION OUTPUT ;
    USE SIGNAL ;
    PORT
      LAYER M3 ;
        RECT  167.112 129.562 167.13 129.6 ;
    END
  END xf[273]
  PIN xf[274]
    DIRECTION OUTPUT ;
    USE SIGNAL ;
    PORT
      LAYER M5 ;
        RECT  167.616 129.516 167.64 129.6 ;
    END
  END xf[274]
  PIN xf[275]
    DIRECTION OUTPUT ;
    USE SIGNAL ;
    PORT
      LAYER M3 ;
        RECT  168.192 129.562 168.21 129.6 ;
    END
  END xf[275]
  PIN xf[27]
    DIRECTION OUTPUT ;
    USE SIGNAL ;
    PORT
      LAYER M3 ;
        RECT  32.04 129.562 32.058 129.6 ;
    END
  END xf[27]
  PIN xf[28]
    DIRECTION OUTPUT ;
    USE SIGNAL ;
    PORT
      LAYER M5 ;
        RECT  32.544 129.516 32.568 129.6 ;
    END
  END xf[28]
  PIN xf[29]
    DIRECTION OUTPUT ;
    USE SIGNAL ;
    PORT
      LAYER M3 ;
        RECT  33.12 129.562 33.138 129.6 ;
    END
  END xf[29]
  PIN xf[2]
    DIRECTION OUTPUT ;
    USE SIGNAL ;
    PORT
      LAYER M5 ;
        RECT  18.336 129.516 18.36 129.6 ;
    END
  END xf[2]
  PIN xf[30]
    DIRECTION OUTPUT ;
    USE SIGNAL ;
    PORT
      LAYER M5 ;
        RECT  33.696 129.516 33.72 129.6 ;
    END
  END xf[30]
  PIN xf[31]
    DIRECTION OUTPUT ;
    USE SIGNAL ;
    PORT
      LAYER M3 ;
        RECT  34.2 129.562 34.218 129.6 ;
    END
  END xf[31]
  PIN xf[32]
    DIRECTION OUTPUT ;
    USE SIGNAL ;
    PORT
      LAYER M5 ;
        RECT  34.752 129.516 34.776 129.6 ;
    END
  END xf[32]
  PIN xf[33]
    DIRECTION OUTPUT ;
    USE SIGNAL ;
    PORT
      LAYER M3 ;
        RECT  35.352 129.562 35.37 129.6 ;
    END
  END xf[33]
  PIN xf[34]
    DIRECTION OUTPUT ;
    USE SIGNAL ;
    PORT
      LAYER M5 ;
        RECT  35.904 129.516 35.928 129.6 ;
    END
  END xf[34]
  PIN xf[35]
    DIRECTION OUTPUT ;
    USE SIGNAL ;
    PORT
      LAYER M3 ;
        RECT  36.432 129.562 36.45 129.6 ;
    END
  END xf[35]
  PIN xf[36]
    DIRECTION OUTPUT ;
    USE SIGNAL ;
    PORT
      LAYER M5 ;
        RECT  36.96 129.516 36.984 129.6 ;
    END
  END xf[36]
  PIN xf[37]
    DIRECTION OUTPUT ;
    USE SIGNAL ;
    PORT
      LAYER M3 ;
        RECT  37.512 129.562 37.53 129.6 ;
    END
  END xf[37]
  PIN xf[38]
    DIRECTION OUTPUT ;
    USE SIGNAL ;
    PORT
      LAYER M5 ;
        RECT  38.112 129.516 38.136 129.6 ;
    END
  END xf[38]
  PIN xf[39]
    DIRECTION OUTPUT ;
    USE SIGNAL ;
    PORT
      LAYER M3 ;
        RECT  38.592 129.562 38.61 129.6 ;
    END
  END xf[39]
  PIN xf[3]
    DIRECTION OUTPUT ;
    USE SIGNAL ;
    PORT
      LAYER M3 ;
        RECT  18.864 129.562 18.882 129.6 ;
    END
  END xf[3]
  PIN xf[40]
    DIRECTION OUTPUT ;
    USE SIGNAL ;
    PORT
      LAYER M5 ;
        RECT  39.168 129.516 39.192 129.6 ;
    END
  END xf[40]
  PIN xf[41]
    DIRECTION OUTPUT ;
    USE SIGNAL ;
    PORT
      LAYER M3 ;
        RECT  39.744 129.562 39.762 129.6 ;
    END
  END xf[41]
  PIN xf[42]
    DIRECTION OUTPUT ;
    USE SIGNAL ;
    PORT
      LAYER M5 ;
        RECT  40.224 129.516 40.248 129.6 ;
    END
  END xf[42]
  PIN xf[43]
    DIRECTION OUTPUT ;
    USE SIGNAL ;
    PORT
      LAYER M3 ;
        RECT  40.824 129.562 40.842 129.6 ;
    END
  END xf[43]
  PIN xf[44]
    DIRECTION OUTPUT ;
    USE SIGNAL ;
    PORT
      LAYER M5 ;
        RECT  41.376 129.516 41.4 129.6 ;
    END
  END xf[44]
  PIN xf[45]
    DIRECTION OUTPUT ;
    USE SIGNAL ;
    PORT
      LAYER M3 ;
        RECT  41.904 129.562 41.922 129.6 ;
    END
  END xf[45]
  PIN xf[46]
    DIRECTION OUTPUT ;
    USE SIGNAL ;
    PORT
      LAYER M5 ;
        RECT  42.432 129.516 42.456 129.6 ;
    END
  END xf[46]
  PIN xf[47]
    DIRECTION OUTPUT ;
    USE SIGNAL ;
    PORT
      LAYER M3 ;
        RECT  42.984 129.562 43.002 129.6 ;
    END
  END xf[47]
  PIN xf[48]
    DIRECTION OUTPUT ;
    USE SIGNAL ;
    PORT
      LAYER M5 ;
        RECT  43.584 129.516 43.608 129.6 ;
    END
  END xf[48]
  PIN xf[49]
    DIRECTION OUTPUT ;
    USE SIGNAL ;
    PORT
      LAYER M3 ;
        RECT  44.136 129.562 44.154 129.6 ;
    END
  END xf[49]
  PIN xf[4]
    DIRECTION OUTPUT ;
    USE SIGNAL ;
    PORT
      LAYER M5 ;
        RECT  19.392 129.516 19.416 129.6 ;
    END
  END xf[4]
  PIN xf[50]
    DIRECTION OUTPUT ;
    USE SIGNAL ;
    PORT
      LAYER M5 ;
        RECT  44.64 129.516 44.664 129.6 ;
    END
  END xf[50]
  PIN xf[51]
    DIRECTION OUTPUT ;
    USE SIGNAL ;
    PORT
      LAYER M3 ;
        RECT  45.216 129.562 45.234 129.6 ;
    END
  END xf[51]
  PIN xf[52]
    DIRECTION OUTPUT ;
    USE SIGNAL ;
    PORT
      LAYER M5 ;
        RECT  45.792 129.516 45.816 129.6 ;
    END
  END xf[52]
  PIN xf[53]
    DIRECTION OUTPUT ;
    USE SIGNAL ;
    PORT
      LAYER M3 ;
        RECT  46.296 129.562 46.314 129.6 ;
    END
  END xf[53]
  PIN xf[54]
    DIRECTION OUTPUT ;
    USE SIGNAL ;
    PORT
      LAYER M5 ;
        RECT  46.848 129.516 46.872 129.6 ;
    END
  END xf[54]
  PIN xf[55]
    DIRECTION OUTPUT ;
    USE SIGNAL ;
    PORT
      LAYER M3 ;
        RECT  47.376 129.562 47.394 129.6 ;
    END
  END xf[55]
  PIN xf[56]
    DIRECTION OUTPUT ;
    USE SIGNAL ;
    PORT
      LAYER M5 ;
        RECT  48 129.516 48.024 129.6 ;
    END
  END xf[56]
  PIN xf[57]
    DIRECTION OUTPUT ;
    USE SIGNAL ;
    PORT
      LAYER M3 ;
        RECT  48.528 129.562 48.546 129.6 ;
    END
  END xf[57]
  PIN xf[58]
    DIRECTION OUTPUT ;
    USE SIGNAL ;
    PORT
      LAYER M5 ;
        RECT  49.056 129.516 49.08 129.6 ;
    END
  END xf[58]
  PIN xf[59]
    DIRECTION OUTPUT ;
    USE SIGNAL ;
    PORT
      LAYER M3 ;
        RECT  49.608 129.562 49.626 129.6 ;
    END
  END xf[59]
  PIN xf[5]
    DIRECTION OUTPUT ;
    USE SIGNAL ;
    PORT
      LAYER M3 ;
        RECT  19.944 129.562 19.962 129.6 ;
    END
  END xf[5]
  PIN xf[60]
    DIRECTION OUTPUT ;
    USE SIGNAL ;
    PORT
      LAYER M5 ;
        RECT  50.112 129.516 50.136 129.6 ;
    END
  END xf[60]
  PIN xf[61]
    DIRECTION OUTPUT ;
    USE SIGNAL ;
    PORT
      LAYER M3 ;
        RECT  50.688 129.562 50.706 129.6 ;
    END
  END xf[61]
  PIN xf[62]
    DIRECTION OUTPUT ;
    USE SIGNAL ;
    PORT
      LAYER M5 ;
        RECT  51.264 129.516 51.288 129.6 ;
    END
  END xf[62]
  PIN xf[63]
    DIRECTION OUTPUT ;
    USE SIGNAL ;
    PORT
      LAYER M3 ;
        RECT  51.768 129.562 51.786 129.6 ;
    END
  END xf[63]
  PIN xf[64]
    DIRECTION OUTPUT ;
    USE SIGNAL ;
    PORT
      LAYER M5 ;
        RECT  52.32 129.516 52.344 129.6 ;
    END
  END xf[64]
  PIN xf[65]
    DIRECTION OUTPUT ;
    USE SIGNAL ;
    PORT
      LAYER M3 ;
        RECT  52.92 129.562 52.938 129.6 ;
    END
  END xf[65]
  PIN xf[66]
    DIRECTION OUTPUT ;
    USE SIGNAL ;
    PORT
      LAYER M5 ;
        RECT  53.472 129.516 53.496 129.6 ;
    END
  END xf[66]
  PIN xf[67]
    DIRECTION OUTPUT ;
    USE SIGNAL ;
    PORT
      LAYER M3 ;
        RECT  54 129.562 54.018 129.6 ;
    END
  END xf[67]
  PIN xf[68]
    DIRECTION OUTPUT ;
    USE SIGNAL ;
    PORT
      LAYER M5 ;
        RECT  54.528 129.516 54.552 129.6 ;
    END
  END xf[68]
  PIN xf[69]
    DIRECTION OUTPUT ;
    USE SIGNAL ;
    PORT
      LAYER M3 ;
        RECT  55.08 129.562 55.098 129.6 ;
    END
  END xf[69]
  PIN xf[6]
    DIRECTION OUTPUT ;
    USE SIGNAL ;
    PORT
      LAYER M5 ;
        RECT  20.544 129.516 20.568 129.6 ;
    END
  END xf[6]
  PIN xf[70]
    DIRECTION OUTPUT ;
    USE SIGNAL ;
    PORT
      LAYER M5 ;
        RECT  55.68 129.516 55.704 129.6 ;
    END
  END xf[70]
  PIN xf[71]
    DIRECTION OUTPUT ;
    USE SIGNAL ;
    PORT
      LAYER M3 ;
        RECT  56.16 129.562 56.178 129.6 ;
    END
  END xf[71]
  PIN xf[72]
    DIRECTION OUTPUT ;
    USE SIGNAL ;
    PORT
      LAYER M5 ;
        RECT  56.736 129.516 56.76 129.6 ;
    END
  END xf[72]
  PIN xf[73]
    DIRECTION OUTPUT ;
    USE SIGNAL ;
    PORT
      LAYER M3 ;
        RECT  57.312 129.562 57.33 129.6 ;
    END
  END xf[73]
  PIN xf[74]
    DIRECTION OUTPUT ;
    USE SIGNAL ;
    PORT
      LAYER M5 ;
        RECT  57.792 129.516 57.816 129.6 ;
    END
  END xf[74]
  PIN xf[75]
    DIRECTION OUTPUT ;
    USE SIGNAL ;
    PORT
      LAYER M3 ;
        RECT  58.392 129.562 58.41 129.6 ;
    END
  END xf[75]
  PIN xf[76]
    DIRECTION OUTPUT ;
    USE SIGNAL ;
    PORT
      LAYER M5 ;
        RECT  58.944 129.516 58.968 129.6 ;
    END
  END xf[76]
  PIN xf[77]
    DIRECTION OUTPUT ;
    USE SIGNAL ;
    PORT
      LAYER M3 ;
        RECT  59.472 129.562 59.49 129.6 ;
    END
  END xf[77]
  PIN xf[78]
    DIRECTION OUTPUT ;
    USE SIGNAL ;
    PORT
      LAYER M5 ;
        RECT  60 129.516 60.024 129.6 ;
    END
  END xf[78]
  PIN xf[79]
    DIRECTION OUTPUT ;
    USE SIGNAL ;
    PORT
      LAYER M3 ;
        RECT  60.552 129.562 60.57 129.6 ;
    END
  END xf[79]
  PIN xf[7]
    DIRECTION OUTPUT ;
    USE SIGNAL ;
    PORT
      LAYER M3 ;
        RECT  21.024 129.562 21.042 129.6 ;
    END
  END xf[7]
  PIN xf[80]
    DIRECTION OUTPUT ;
    USE SIGNAL ;
    PORT
      LAYER M5 ;
        RECT  61.152 129.516 61.176 129.6 ;
    END
  END xf[80]
  PIN xf[81]
    DIRECTION OUTPUT ;
    USE SIGNAL ;
    PORT
      LAYER M3 ;
        RECT  61.704 129.562 61.722 129.6 ;
    END
  END xf[81]
  PIN xf[82]
    DIRECTION OUTPUT ;
    USE SIGNAL ;
    PORT
      LAYER M5 ;
        RECT  62.208 129.516 62.232 129.6 ;
    END
  END xf[82]
  PIN xf[83]
    DIRECTION OUTPUT ;
    USE SIGNAL ;
    PORT
      LAYER M3 ;
        RECT  62.784 129.562 62.802 129.6 ;
    END
  END xf[83]
  PIN xf[84]
    DIRECTION OUTPUT ;
    USE SIGNAL ;
    PORT
      LAYER M5 ;
        RECT  63.36 129.516 63.384 129.6 ;
    END
  END xf[84]
  PIN xf[85]
    DIRECTION OUTPUT ;
    USE SIGNAL ;
    PORT
      LAYER M3 ;
        RECT  63.864 129.562 63.882 129.6 ;
    END
  END xf[85]
  PIN xf[86]
    DIRECTION OUTPUT ;
    USE SIGNAL ;
    PORT
      LAYER M5 ;
        RECT  64.416 129.516 64.44 129.6 ;
    END
  END xf[86]
  PIN xf[87]
    DIRECTION OUTPUT ;
    USE SIGNAL ;
    PORT
      LAYER M3 ;
        RECT  64.944 129.562 64.962 129.6 ;
    END
  END xf[87]
  PIN xf[88]
    DIRECTION OUTPUT ;
    USE SIGNAL ;
    PORT
      LAYER M5 ;
        RECT  65.568 129.516 65.592 129.6 ;
    END
  END xf[88]
  PIN xf[89]
    DIRECTION OUTPUT ;
    USE SIGNAL ;
    PORT
      LAYER M3 ;
        RECT  66.096 129.562 66.114 129.6 ;
    END
  END xf[89]
  PIN xf[8]
    DIRECTION OUTPUT ;
    USE SIGNAL ;
    PORT
      LAYER M5 ;
        RECT  21.6 129.516 21.624 129.6 ;
    END
  END xf[8]
  PIN xf[90]
    DIRECTION OUTPUT ;
    USE SIGNAL ;
    PORT
      LAYER M5 ;
        RECT  66.624 129.516 66.648 129.6 ;
    END
  END xf[90]
  PIN xf[91]
    DIRECTION OUTPUT ;
    USE SIGNAL ;
    PORT
      LAYER M3 ;
        RECT  67.176 129.562 67.194 129.6 ;
    END
  END xf[91]
  PIN xf[92]
    DIRECTION OUTPUT ;
    USE SIGNAL ;
    PORT
      LAYER M5 ;
        RECT  67.68 129.516 67.704 129.6 ;
    END
  END xf[92]
  PIN xf[93]
    DIRECTION OUTPUT ;
    USE SIGNAL ;
    PORT
      LAYER M3 ;
        RECT  68.256 129.562 68.274 129.6 ;
    END
  END xf[93]
  PIN xf[94]
    DIRECTION OUTPUT ;
    USE SIGNAL ;
    PORT
      LAYER M5 ;
        RECT  68.832 129.516 68.856 129.6 ;
    END
  END xf[94]
  PIN xf[95]
    DIRECTION OUTPUT ;
    USE SIGNAL ;
    PORT
      LAYER M3 ;
        RECT  69.336 129.562 69.354 129.6 ;
    END
  END xf[95]
  PIN xf[96]
    DIRECTION OUTPUT ;
    USE SIGNAL ;
    PORT
      LAYER M5 ;
        RECT  69.888 129.516 69.912 129.6 ;
    END
  END xf[96]
  PIN xf[97]
    DIRECTION OUTPUT ;
    USE SIGNAL ;
    PORT
      LAYER M3 ;
        RECT  70.488 129.562 70.506 129.6 ;
    END
  END xf[97]
  PIN xf[98]
    DIRECTION OUTPUT ;
    USE SIGNAL ;
    PORT
      LAYER M5 ;
        RECT  71.04 129.516 71.064 129.6 ;
    END
  END xf[98]
  PIN xf[99]
    DIRECTION OUTPUT ;
    USE SIGNAL ;
    PORT
      LAYER M3 ;
        RECT  71.568 129.562 71.586 129.6 ;
    END
  END xf[99]
  PIN xf[9]
    DIRECTION OUTPUT ;
    USE SIGNAL ;
    PORT
      LAYER M3 ;
        RECT  22.176 129.562 22.194 129.6 ;
    END
  END xf[9]
  PIN xf_s
    DIRECTION OUTPUT ;
    USE SIGNAL ;
    PORT
      LAYER M3 ;
        RECT  16.632 129.562 16.65 129.6 ;
    END
  END xf_s
  PIN xf_v
    DIRECTION OUTPUT ;
    USE SIGNAL ;
    PORT
      LAYER M5 ;
        RECT  16.128 129.516 16.152 129.6 ;
    END
  END xf_v
  PIN y[0]
    DIRECTION INPUT ;
    USE SIGNAL ;
    PORT
      LAYER M4 ;
        RECT  0 6.432 0.084 6.456 ;
    END
  END y[0]
  PIN y[100]
    DIRECTION INPUT ;
    USE SIGNAL ;
    PORT
      LAYER M4 ;
        RECT  0 52.896 0.084 52.92 ;
    END
  END y[100]
  PIN y[101]
    DIRECTION INPUT ;
    USE SIGNAL ;
    PORT
      LAYER M4 ;
        RECT  0 53.376 0.084 53.4 ;
    END
  END y[101]
  PIN y[102]
    DIRECTION INPUT ;
    USE SIGNAL ;
    PORT
      LAYER M4 ;
        RECT  0 53.856 0.084 53.88 ;
    END
  END y[102]
  PIN y[103]
    DIRECTION INPUT ;
    USE SIGNAL ;
    PORT
      LAYER M4 ;
        RECT  0 54.336 0.084 54.36 ;
    END
  END y[103]
  PIN y[104]
    DIRECTION INPUT ;
    USE SIGNAL ;
    PORT
      LAYER M4 ;
        RECT  0 54.816 0.084 54.84 ;
    END
  END y[104]
  PIN y[105]
    DIRECTION INPUT ;
    USE SIGNAL ;
    PORT
      LAYER M4 ;
        RECT  0 55.296 0.084 55.32 ;
    END
  END y[105]
  PIN y[106]
    DIRECTION INPUT ;
    USE SIGNAL ;
    PORT
      LAYER M4 ;
        RECT  0 55.68 0.084 55.704 ;
    END
  END y[106]
  PIN y[107]
    DIRECTION INPUT ;
    USE SIGNAL ;
    PORT
      LAYER M4 ;
        RECT  0 56.16 0.084 56.184 ;
    END
  END y[107]
  PIN y[108]
    DIRECTION INPUT ;
    USE SIGNAL ;
    PORT
      LAYER M4 ;
        RECT  0 56.64 0.084 56.664 ;
    END
  END y[108]
  PIN y[109]
    DIRECTION INPUT ;
    USE SIGNAL ;
    PORT
      LAYER M4 ;
        RECT  0 57.12 0.084 57.144 ;
    END
  END y[109]
  PIN y[10]
    DIRECTION INPUT ;
    USE SIGNAL ;
    PORT
      LAYER M4 ;
        RECT  0 11.04 0.084 11.064 ;
    END
  END y[10]
  PIN y[110]
    DIRECTION INPUT ;
    USE SIGNAL ;
    PORT
      LAYER M4 ;
        RECT  0 57.6 0.084 57.624 ;
    END
  END y[110]
  PIN y[111]
    DIRECTION INPUT ;
    USE SIGNAL ;
    PORT
      LAYER M4 ;
        RECT  0 58.08 0.084 58.104 ;
    END
  END y[111]
  PIN y[112]
    DIRECTION INPUT ;
    USE SIGNAL ;
    PORT
      LAYER M4 ;
        RECT  0 58.464 0.084 58.488 ;
    END
  END y[112]
  PIN y[113]
    DIRECTION INPUT ;
    USE SIGNAL ;
    PORT
      LAYER M4 ;
        RECT  0 58.944 0.084 58.968 ;
    END
  END y[113]
  PIN y[114]
    DIRECTION INPUT ;
    USE SIGNAL ;
    PORT
      LAYER M4 ;
        RECT  0 59.424 0.084 59.448 ;
    END
  END y[114]
  PIN y[115]
    DIRECTION INPUT ;
    USE SIGNAL ;
    PORT
      LAYER M4 ;
        RECT  0 59.904 0.084 59.928 ;
    END
  END y[115]
  PIN y[116]
    DIRECTION INPUT ;
    USE SIGNAL ;
    PORT
      LAYER M4 ;
        RECT  0 60.384 0.084 60.408 ;
    END
  END y[116]
  PIN y[117]
    DIRECTION INPUT ;
    USE SIGNAL ;
    PORT
      LAYER M4 ;
        RECT  0 60.864 0.084 60.888 ;
    END
  END y[117]
  PIN y[118]
    DIRECTION INPUT ;
    USE SIGNAL ;
    PORT
      LAYER M4 ;
        RECT  0 61.344 0.084 61.368 ;
    END
  END y[118]
  PIN y[119]
    DIRECTION INPUT ;
    USE SIGNAL ;
    PORT
      LAYER M4 ;
        RECT  0 61.728 0.084 61.752 ;
    END
  END y[119]
  PIN y[11]
    DIRECTION INPUT ;
    USE SIGNAL ;
    PORT
      LAYER M4 ;
        RECT  0 11.52 0.084 11.544 ;
    END
  END y[11]
  PIN y[120]
    DIRECTION INPUT ;
    USE SIGNAL ;
    PORT
      LAYER M4 ;
        RECT  0 62.208 0.084 62.232 ;
    END
  END y[120]
  PIN y[121]
    DIRECTION INPUT ;
    USE SIGNAL ;
    PORT
      LAYER M4 ;
        RECT  0 62.688 0.084 62.712 ;
    END
  END y[121]
  PIN y[122]
    DIRECTION INPUT ;
    USE SIGNAL ;
    PORT
      LAYER M4 ;
        RECT  0 63.168 0.084 63.192 ;
    END
  END y[122]
  PIN y[123]
    DIRECTION INPUT ;
    USE SIGNAL ;
    PORT
      LAYER M4 ;
        RECT  0 63.648 0.084 63.672 ;
    END
  END y[123]
  PIN y[124]
    DIRECTION INPUT ;
    USE SIGNAL ;
    PORT
      LAYER M4 ;
        RECT  0 64.128 0.084 64.152 ;
    END
  END y[124]
  PIN y[125]
    DIRECTION INPUT ;
    USE SIGNAL ;
    PORT
      LAYER M4 ;
        RECT  0 64.512 0.084 64.536 ;
    END
  END y[125]
  PIN y[126]
    DIRECTION INPUT ;
    USE SIGNAL ;
    PORT
      LAYER M4 ;
        RECT  0 64.992 0.084 65.016 ;
    END
  END y[126]
  PIN y[127]
    DIRECTION INPUT ;
    USE SIGNAL ;
    PORT
      LAYER M4 ;
        RECT  0 65.472 0.084 65.496 ;
    END
  END y[127]
  PIN y[128]
    DIRECTION INPUT ;
    USE SIGNAL ;
    PORT
      LAYER M4 ;
        RECT  0 65.952 0.084 65.976 ;
    END
  END y[128]
  PIN y[129]
    DIRECTION INPUT ;
    USE SIGNAL ;
    PORT
      LAYER M4 ;
        RECT  0 66.432 0.084 66.456 ;
    END
  END y[129]
  PIN y[12]
    DIRECTION INPUT ;
    USE SIGNAL ;
    PORT
      LAYER M4 ;
        RECT  0 12 0.084 12.024 ;
    END
  END y[12]
  PIN y[130]
    DIRECTION INPUT ;
    USE SIGNAL ;
    PORT
      LAYER M4 ;
        RECT  0 66.912 0.084 66.936 ;
    END
  END y[130]
  PIN y[131]
    DIRECTION INPUT ;
    USE SIGNAL ;
    PORT
      LAYER M4 ;
        RECT  0 67.392 0.084 67.416 ;
    END
  END y[131]
  PIN y[132]
    DIRECTION INPUT ;
    USE SIGNAL ;
    PORT
      LAYER M4 ;
        RECT  0 67.776 0.084 67.8 ;
    END
  END y[132]
  PIN y[133]
    DIRECTION INPUT ;
    USE SIGNAL ;
    PORT
      LAYER M4 ;
        RECT  0 68.256 0.084 68.28 ;
    END
  END y[133]
  PIN y[134]
    DIRECTION INPUT ;
    USE SIGNAL ;
    PORT
      LAYER M4 ;
        RECT  0 68.736 0.084 68.76 ;
    END
  END y[134]
  PIN y[135]
    DIRECTION INPUT ;
    USE SIGNAL ;
    PORT
      LAYER M4 ;
        RECT  0 69.216 0.084 69.24 ;
    END
  END y[135]
  PIN y[136]
    DIRECTION INPUT ;
    USE SIGNAL ;
    PORT
      LAYER M4 ;
        RECT  0 69.696 0.084 69.72 ;
    END
  END y[136]
  PIN y[137]
    DIRECTION INPUT ;
    USE SIGNAL ;
    PORT
      LAYER M4 ;
        RECT  0 70.176 0.084 70.2 ;
    END
  END y[137]
  PIN y[138]
    DIRECTION INPUT ;
    USE SIGNAL ;
    PORT
      LAYER M4 ;
        RECT  0 70.56 0.084 70.584 ;
    END
  END y[138]
  PIN y[139]
    DIRECTION INPUT ;
    USE SIGNAL ;
    PORT
      LAYER M4 ;
        RECT  0 71.04 0.084 71.064 ;
    END
  END y[139]
  PIN y[13]
    DIRECTION INPUT ;
    USE SIGNAL ;
    PORT
      LAYER M4 ;
        RECT  0 12.48 0.084 12.504 ;
    END
  END y[13]
  PIN y[140]
    DIRECTION INPUT ;
    USE SIGNAL ;
    PORT
      LAYER M4 ;
        RECT  0 71.52 0.084 71.544 ;
    END
  END y[140]
  PIN y[141]
    DIRECTION INPUT ;
    USE SIGNAL ;
    PORT
      LAYER M4 ;
        RECT  0 72 0.084 72.024 ;
    END
  END y[141]
  PIN y[142]
    DIRECTION INPUT ;
    USE SIGNAL ;
    PORT
      LAYER M4 ;
        RECT  0 72.48 0.084 72.504 ;
    END
  END y[142]
  PIN y[143]
    DIRECTION INPUT ;
    USE SIGNAL ;
    PORT
      LAYER M4 ;
        RECT  0 72.96 0.084 72.984 ;
    END
  END y[143]
  PIN y[144]
    DIRECTION INPUT ;
    USE SIGNAL ;
    PORT
      LAYER M4 ;
        RECT  0 73.44 0.084 73.464 ;
    END
  END y[144]
  PIN y[145]
    DIRECTION INPUT ;
    USE SIGNAL ;
    PORT
      LAYER M4 ;
        RECT  0 73.824 0.084 73.848 ;
    END
  END y[145]
  PIN y[146]
    DIRECTION INPUT ;
    USE SIGNAL ;
    PORT
      LAYER M4 ;
        RECT  0 74.304 0.084 74.328 ;
    END
  END y[146]
  PIN y[147]
    DIRECTION INPUT ;
    USE SIGNAL ;
    PORT
      LAYER M4 ;
        RECT  0 74.784 0.084 74.808 ;
    END
  END y[147]
  PIN y[148]
    DIRECTION INPUT ;
    USE SIGNAL ;
    PORT
      LAYER M4 ;
        RECT  0 75.264 0.084 75.288 ;
    END
  END y[148]
  PIN y[149]
    DIRECTION INPUT ;
    USE SIGNAL ;
    PORT
      LAYER M4 ;
        RECT  0 75.744 0.084 75.768 ;
    END
  END y[149]
  PIN y[14]
    DIRECTION INPUT ;
    USE SIGNAL ;
    PORT
      LAYER M4 ;
        RECT  0 12.96 0.084 12.984 ;
    END
  END y[14]
  PIN y[150]
    DIRECTION INPUT ;
    USE SIGNAL ;
    PORT
      LAYER M4 ;
        RECT  0 76.224 0.084 76.248 ;
    END
  END y[150]
  PIN y[151]
    DIRECTION INPUT ;
    USE SIGNAL ;
    PORT
      LAYER M4 ;
        RECT  0 76.608 0.084 76.632 ;
    END
  END y[151]
  PIN y[152]
    DIRECTION INPUT ;
    USE SIGNAL ;
    PORT
      LAYER M4 ;
        RECT  0 77.088 0.084 77.112 ;
    END
  END y[152]
  PIN y[153]
    DIRECTION INPUT ;
    USE SIGNAL ;
    PORT
      LAYER M4 ;
        RECT  0 77.568 0.084 77.592 ;
    END
  END y[153]
  PIN y[154]
    DIRECTION INPUT ;
    USE SIGNAL ;
    PORT
      LAYER M4 ;
        RECT  0 78.048 0.084 78.072 ;
    END
  END y[154]
  PIN y[155]
    DIRECTION INPUT ;
    USE SIGNAL ;
    PORT
      LAYER M4 ;
        RECT  0 78.528 0.084 78.552 ;
    END
  END y[155]
  PIN y[156]
    DIRECTION INPUT ;
    USE SIGNAL ;
    PORT
      LAYER M4 ;
        RECT  0 79.008 0.084 79.032 ;
    END
  END y[156]
  PIN y[157]
    DIRECTION INPUT ;
    USE SIGNAL ;
    PORT
      LAYER M4 ;
        RECT  0 79.488 0.084 79.512 ;
    END
  END y[157]
  PIN y[158]
    DIRECTION INPUT ;
    USE SIGNAL ;
    PORT
      LAYER M4 ;
        RECT  0 79.872 0.084 79.896 ;
    END
  END y[158]
  PIN y[159]
    DIRECTION INPUT ;
    USE SIGNAL ;
    PORT
      LAYER M4 ;
        RECT  0 80.352 0.084 80.376 ;
    END
  END y[159]
  PIN y[15]
    DIRECTION INPUT ;
    USE SIGNAL ;
    PORT
      LAYER M4 ;
        RECT  0 13.344 0.084 13.368 ;
    END
  END y[15]
  PIN y[160]
    DIRECTION INPUT ;
    USE SIGNAL ;
    PORT
      LAYER M4 ;
        RECT  0 80.832 0.084 80.856 ;
    END
  END y[160]
  PIN y[161]
    DIRECTION INPUT ;
    USE SIGNAL ;
    PORT
      LAYER M4 ;
        RECT  0 81.312 0.084 81.336 ;
    END
  END y[161]
  PIN y[162]
    DIRECTION INPUT ;
    USE SIGNAL ;
    PORT
      LAYER M4 ;
        RECT  0 81.792 0.084 81.816 ;
    END
  END y[162]
  PIN y[163]
    DIRECTION INPUT ;
    USE SIGNAL ;
    PORT
      LAYER M4 ;
        RECT  0 82.272 0.084 82.296 ;
    END
  END y[163]
  PIN y[164]
    DIRECTION INPUT ;
    USE SIGNAL ;
    PORT
      LAYER M4 ;
        RECT  0 82.656 0.084 82.68 ;
    END
  END y[164]
  PIN y[165]
    DIRECTION INPUT ;
    USE SIGNAL ;
    PORT
      LAYER M4 ;
        RECT  0 83.136 0.084 83.16 ;
    END
  END y[165]
  PIN y[166]
    DIRECTION INPUT ;
    USE SIGNAL ;
    PORT
      LAYER M4 ;
        RECT  0 83.616 0.084 83.64 ;
    END
  END y[166]
  PIN y[167]
    DIRECTION INPUT ;
    USE SIGNAL ;
    PORT
      LAYER M4 ;
        RECT  0 84.096 0.084 84.12 ;
    END
  END y[167]
  PIN y[168]
    DIRECTION INPUT ;
    USE SIGNAL ;
    PORT
      LAYER M4 ;
        RECT  0 84.576 0.084 84.6 ;
    END
  END y[168]
  PIN y[169]
    DIRECTION INPUT ;
    USE SIGNAL ;
    PORT
      LAYER M4 ;
        RECT  0 85.056 0.084 85.08 ;
    END
  END y[169]
  PIN y[16]
    DIRECTION INPUT ;
    USE SIGNAL ;
    PORT
      LAYER M4 ;
        RECT  0 13.824 0.084 13.848 ;
    END
  END y[16]
  PIN y[170]
    DIRECTION INPUT ;
    USE SIGNAL ;
    PORT
      LAYER M4 ;
        RECT  0 85.536 0.084 85.56 ;
    END
  END y[170]
  PIN y[171]
    DIRECTION INPUT ;
    USE SIGNAL ;
    PORT
      LAYER M4 ;
        RECT  0 85.92 0.084 85.944 ;
    END
  END y[171]
  PIN y[172]
    DIRECTION INPUT ;
    USE SIGNAL ;
    PORT
      LAYER M4 ;
        RECT  0 86.4 0.084 86.424 ;
    END
  END y[172]
  PIN y[173]
    DIRECTION INPUT ;
    USE SIGNAL ;
    PORT
      LAYER M4 ;
        RECT  0 86.88 0.084 86.904 ;
    END
  END y[173]
  PIN y[174]
    DIRECTION INPUT ;
    USE SIGNAL ;
    PORT
      LAYER M4 ;
        RECT  0 87.36 0.084 87.384 ;
    END
  END y[174]
  PIN y[175]
    DIRECTION INPUT ;
    USE SIGNAL ;
    PORT
      LAYER M4 ;
        RECT  0 87.84 0.084 87.864 ;
    END
  END y[175]
  PIN y[176]
    DIRECTION INPUT ;
    USE SIGNAL ;
    PORT
      LAYER M4 ;
        RECT  0 88.32 0.084 88.344 ;
    END
  END y[176]
  PIN y[177]
    DIRECTION INPUT ;
    USE SIGNAL ;
    PORT
      LAYER M4 ;
        RECT  0 88.704 0.084 88.728 ;
    END
  END y[177]
  PIN y[178]
    DIRECTION INPUT ;
    USE SIGNAL ;
    PORT
      LAYER M4 ;
        RECT  0 89.184 0.084 89.208 ;
    END
  END y[178]
  PIN y[179]
    DIRECTION INPUT ;
    USE SIGNAL ;
    PORT
      LAYER M4 ;
        RECT  0 89.664 0.084 89.688 ;
    END
  END y[179]
  PIN y[17]
    DIRECTION INPUT ;
    USE SIGNAL ;
    PORT
      LAYER M4 ;
        RECT  0 14.304 0.084 14.328 ;
    END
  END y[17]
  PIN y[180]
    DIRECTION INPUT ;
    USE SIGNAL ;
    PORT
      LAYER M4 ;
        RECT  0 90.144 0.084 90.168 ;
    END
  END y[180]
  PIN y[181]
    DIRECTION INPUT ;
    USE SIGNAL ;
    PORT
      LAYER M4 ;
        RECT  0 90.624 0.084 90.648 ;
    END
  END y[181]
  PIN y[182]
    DIRECTION INPUT ;
    USE SIGNAL ;
    PORT
      LAYER M4 ;
        RECT  0 91.104 0.084 91.128 ;
    END
  END y[182]
  PIN y[183]
    DIRECTION INPUT ;
    USE SIGNAL ;
    PORT
      LAYER M4 ;
        RECT  0 91.584 0.084 91.608 ;
    END
  END y[183]
  PIN y[184]
    DIRECTION INPUT ;
    USE SIGNAL ;
    PORT
      LAYER M4 ;
        RECT  0 91.968 0.084 91.992 ;
    END
  END y[184]
  PIN y[185]
    DIRECTION INPUT ;
    USE SIGNAL ;
    PORT
      LAYER M4 ;
        RECT  0 92.448 0.084 92.472 ;
    END
  END y[185]
  PIN y[186]
    DIRECTION INPUT ;
    USE SIGNAL ;
    PORT
      LAYER M4 ;
        RECT  0 92.928 0.084 92.952 ;
    END
  END y[186]
  PIN y[187]
    DIRECTION INPUT ;
    USE SIGNAL ;
    PORT
      LAYER M4 ;
        RECT  0 93.408 0.084 93.432 ;
    END
  END y[187]
  PIN y[188]
    DIRECTION INPUT ;
    USE SIGNAL ;
    PORT
      LAYER M4 ;
        RECT  0 93.888 0.084 93.912 ;
    END
  END y[188]
  PIN y[189]
    DIRECTION INPUT ;
    USE SIGNAL ;
    PORT
      LAYER M4 ;
        RECT  0 94.368 0.084 94.392 ;
    END
  END y[189]
  PIN y[18]
    DIRECTION INPUT ;
    USE SIGNAL ;
    PORT
      LAYER M4 ;
        RECT  0 14.784 0.084 14.808 ;
    END
  END y[18]
  PIN y[190]
    DIRECTION INPUT ;
    USE SIGNAL ;
    PORT
      LAYER M4 ;
        RECT  0 94.752 0.084 94.776 ;
    END
  END y[190]
  PIN y[191]
    DIRECTION INPUT ;
    USE SIGNAL ;
    PORT
      LAYER M4 ;
        RECT  0 95.232 0.084 95.256 ;
    END
  END y[191]
  PIN y[192]
    DIRECTION INPUT ;
    USE SIGNAL ;
    PORT
      LAYER M4 ;
        RECT  0 95.712 0.084 95.736 ;
    END
  END y[192]
  PIN y[193]
    DIRECTION INPUT ;
    USE SIGNAL ;
    PORT
      LAYER M4 ;
        RECT  0 96.192 0.084 96.216 ;
    END
  END y[193]
  PIN y[194]
    DIRECTION INPUT ;
    USE SIGNAL ;
    PORT
      LAYER M4 ;
        RECT  0 96.672 0.084 96.696 ;
    END
  END y[194]
  PIN y[195]
    DIRECTION INPUT ;
    USE SIGNAL ;
    PORT
      LAYER M4 ;
        RECT  0 97.152 0.084 97.176 ;
    END
  END y[195]
  PIN y[196]
    DIRECTION INPUT ;
    USE SIGNAL ;
    PORT
      LAYER M4 ;
        RECT  0 97.632 0.084 97.656 ;
    END
  END y[196]
  PIN y[197]
    DIRECTION INPUT ;
    USE SIGNAL ;
    PORT
      LAYER M4 ;
        RECT  0 98.016 0.084 98.04 ;
    END
  END y[197]
  PIN y[198]
    DIRECTION INPUT ;
    USE SIGNAL ;
    PORT
      LAYER M4 ;
        RECT  0 98.496 0.084 98.52 ;
    END
  END y[198]
  PIN y[199]
    DIRECTION INPUT ;
    USE SIGNAL ;
    PORT
      LAYER M4 ;
        RECT  0 98.976 0.084 99 ;
    END
  END y[199]
  PIN y[19]
    DIRECTION INPUT ;
    USE SIGNAL ;
    PORT
      LAYER M4 ;
        RECT  0 15.264 0.084 15.288 ;
    END
  END y[19]
  PIN y[1]
    DIRECTION INPUT ;
    USE SIGNAL ;
    PORT
      LAYER M4 ;
        RECT  0 6.912 0.084 6.936 ;
    END
  END y[1]
  PIN y[200]
    DIRECTION INPUT ;
    USE SIGNAL ;
    PORT
      LAYER M4 ;
        RECT  0 99.456 0.084 99.48 ;
    END
  END y[200]
  PIN y[201]
    DIRECTION INPUT ;
    USE SIGNAL ;
    PORT
      LAYER M4 ;
        RECT  0 99.936 0.084 99.96 ;
    END
  END y[201]
  PIN y[202]
    DIRECTION INPUT ;
    USE SIGNAL ;
    PORT
      LAYER M4 ;
        RECT  0 100.416 0.084 100.44 ;
    END
  END y[202]
  PIN y[203]
    DIRECTION INPUT ;
    USE SIGNAL ;
    PORT
      LAYER M4 ;
        RECT  0 100.8 0.084 100.824 ;
    END
  END y[203]
  PIN y[204]
    DIRECTION INPUT ;
    USE SIGNAL ;
    PORT
      LAYER M4 ;
        RECT  0 101.28 0.084 101.304 ;
    END
  END y[204]
  PIN y[205]
    DIRECTION INPUT ;
    USE SIGNAL ;
    PORT
      LAYER M4 ;
        RECT  0 101.76 0.084 101.784 ;
    END
  END y[205]
  PIN y[206]
    DIRECTION INPUT ;
    USE SIGNAL ;
    PORT
      LAYER M4 ;
        RECT  0 102.24 0.084 102.264 ;
    END
  END y[206]
  PIN y[207]
    DIRECTION INPUT ;
    USE SIGNAL ;
    PORT
      LAYER M4 ;
        RECT  0 102.72 0.084 102.744 ;
    END
  END y[207]
  PIN y[208]
    DIRECTION INPUT ;
    USE SIGNAL ;
    PORT
      LAYER M4 ;
        RECT  0 103.2 0.084 103.224 ;
    END
  END y[208]
  PIN y[209]
    DIRECTION INPUT ;
    USE SIGNAL ;
    PORT
      LAYER M4 ;
        RECT  0 103.68 0.084 103.704 ;
    END
  END y[209]
  PIN y[20]
    DIRECTION INPUT ;
    USE SIGNAL ;
    PORT
      LAYER M4 ;
        RECT  0 15.744 0.084 15.768 ;
    END
  END y[20]
  PIN y[210]
    DIRECTION INPUT ;
    USE SIGNAL ;
    PORT
      LAYER M4 ;
        RECT  0 104.064 0.084 104.088 ;
    END
  END y[210]
  PIN y[211]
    DIRECTION INPUT ;
    USE SIGNAL ;
    PORT
      LAYER M4 ;
        RECT  0 104.544 0.084 104.568 ;
    END
  END y[211]
  PIN y[212]
    DIRECTION INPUT ;
    USE SIGNAL ;
    PORT
      LAYER M4 ;
        RECT  0 105.024 0.084 105.048 ;
    END
  END y[212]
  PIN y[213]
    DIRECTION INPUT ;
    USE SIGNAL ;
    PORT
      LAYER M4 ;
        RECT  0 105.504 0.084 105.528 ;
    END
  END y[213]
  PIN y[214]
    DIRECTION INPUT ;
    USE SIGNAL ;
    PORT
      LAYER M4 ;
        RECT  0 105.984 0.084 106.008 ;
    END
  END y[214]
  PIN y[215]
    DIRECTION INPUT ;
    USE SIGNAL ;
    PORT
      LAYER M4 ;
        RECT  0 106.464 0.084 106.488 ;
    END
  END y[215]
  PIN y[216]
    DIRECTION INPUT ;
    USE SIGNAL ;
    PORT
      LAYER M4 ;
        RECT  0 106.848 0.084 106.872 ;
    END
  END y[216]
  PIN y[217]
    DIRECTION INPUT ;
    USE SIGNAL ;
    PORT
      LAYER M4 ;
        RECT  0 107.328 0.084 107.352 ;
    END
  END y[217]
  PIN y[218]
    DIRECTION INPUT ;
    USE SIGNAL ;
    PORT
      LAYER M4 ;
        RECT  0 107.808 0.084 107.832 ;
    END
  END y[218]
  PIN y[219]
    DIRECTION INPUT ;
    USE SIGNAL ;
    PORT
      LAYER M4 ;
        RECT  0 108.288 0.084 108.312 ;
    END
  END y[219]
  PIN y[21]
    DIRECTION INPUT ;
    USE SIGNAL ;
    PORT
      LAYER M4 ;
        RECT  0 16.128 0.084 16.152 ;
    END
  END y[21]
  PIN y[220]
    DIRECTION INPUT ;
    USE SIGNAL ;
    PORT
      LAYER M4 ;
        RECT  0 108.768 0.084 108.792 ;
    END
  END y[220]
  PIN y[221]
    DIRECTION INPUT ;
    USE SIGNAL ;
    PORT
      LAYER M4 ;
        RECT  0 109.248 0.084 109.272 ;
    END
  END y[221]
  PIN y[222]
    DIRECTION INPUT ;
    USE SIGNAL ;
    PORT
      LAYER M4 ;
        RECT  0 109.728 0.084 109.752 ;
    END
  END y[222]
  PIN y[223]
    DIRECTION INPUT ;
    USE SIGNAL ;
    PORT
      LAYER M4 ;
        RECT  0 110.112 0.084 110.136 ;
    END
  END y[223]
  PIN y[224]
    DIRECTION INPUT ;
    USE SIGNAL ;
    PORT
      LAYER M4 ;
        RECT  0 110.592 0.084 110.616 ;
    END
  END y[224]
  PIN y[225]
    DIRECTION INPUT ;
    USE SIGNAL ;
    PORT
      LAYER M4 ;
        RECT  0 111.072 0.084 111.096 ;
    END
  END y[225]
  PIN y[226]
    DIRECTION INPUT ;
    USE SIGNAL ;
    PORT
      LAYER M4 ;
        RECT  0 111.552 0.084 111.576 ;
    END
  END y[226]
  PIN y[227]
    DIRECTION INPUT ;
    USE SIGNAL ;
    PORT
      LAYER M4 ;
        RECT  0 112.032 0.084 112.056 ;
    END
  END y[227]
  PIN y[228]
    DIRECTION INPUT ;
    USE SIGNAL ;
    PORT
      LAYER M4 ;
        RECT  0 112.512 0.084 112.536 ;
    END
  END y[228]
  PIN y[229]
    DIRECTION INPUT ;
    USE SIGNAL ;
    PORT
      LAYER M4 ;
        RECT  0 112.896 0.084 112.92 ;
    END
  END y[229]
  PIN y[22]
    DIRECTION INPUT ;
    USE SIGNAL ;
    PORT
      LAYER M4 ;
        RECT  0 16.608 0.084 16.632 ;
    END
  END y[22]
  PIN y[230]
    DIRECTION INPUT ;
    USE SIGNAL ;
    PORT
      LAYER M4 ;
        RECT  0 113.376 0.084 113.4 ;
    END
  END y[230]
  PIN y[231]
    DIRECTION INPUT ;
    USE SIGNAL ;
    PORT
      LAYER M4 ;
        RECT  0 113.856 0.084 113.88 ;
    END
  END y[231]
  PIN y[232]
    DIRECTION INPUT ;
    USE SIGNAL ;
    PORT
      LAYER M4 ;
        RECT  0 114.336 0.084 114.36 ;
    END
  END y[232]
  PIN y[233]
    DIRECTION INPUT ;
    USE SIGNAL ;
    PORT
      LAYER M4 ;
        RECT  0 114.816 0.084 114.84 ;
    END
  END y[233]
  PIN y[234]
    DIRECTION INPUT ;
    USE SIGNAL ;
    PORT
      LAYER M4 ;
        RECT  0 115.296 0.084 115.32 ;
    END
  END y[234]
  PIN y[235]
    DIRECTION INPUT ;
    USE SIGNAL ;
    PORT
      LAYER M4 ;
        RECT  0 115.776 0.084 115.8 ;
    END
  END y[235]
  PIN y[236]
    DIRECTION INPUT ;
    USE SIGNAL ;
    PORT
      LAYER M4 ;
        RECT  0 116.16 0.084 116.184 ;
    END
  END y[236]
  PIN y[237]
    DIRECTION INPUT ;
    USE SIGNAL ;
    PORT
      LAYER M4 ;
        RECT  0 116.64 0.084 116.664 ;
    END
  END y[237]
  PIN y[238]
    DIRECTION INPUT ;
    USE SIGNAL ;
    PORT
      LAYER M4 ;
        RECT  0 117.12 0.084 117.144 ;
    END
  END y[238]
  PIN y[239]
    DIRECTION INPUT ;
    USE SIGNAL ;
    PORT
      LAYER M4 ;
        RECT  0 117.6 0.084 117.624 ;
    END
  END y[239]
  PIN y[23]
    DIRECTION INPUT ;
    USE SIGNAL ;
    PORT
      LAYER M4 ;
        RECT  0 17.088 0.084 17.112 ;
    END
  END y[23]
  PIN y[240]
    DIRECTION INPUT ;
    USE SIGNAL ;
    PORT
      LAYER M4 ;
        RECT  0 118.08 0.084 118.104 ;
    END
  END y[240]
  PIN y[241]
    DIRECTION INPUT ;
    USE SIGNAL ;
    PORT
      LAYER M4 ;
        RECT  0 118.56 0.084 118.584 ;
    END
  END y[241]
  PIN y[242]
    DIRECTION INPUT ;
    USE SIGNAL ;
    PORT
      LAYER M4 ;
        RECT  0 118.944 0.084 118.968 ;
    END
  END y[242]
  PIN y[243]
    DIRECTION INPUT ;
    USE SIGNAL ;
    PORT
      LAYER M4 ;
        RECT  0 119.424 0.084 119.448 ;
    END
  END y[243]
  PIN y[244]
    DIRECTION INPUT ;
    USE SIGNAL ;
    PORT
      LAYER M4 ;
        RECT  0 119.904 0.084 119.928 ;
    END
  END y[244]
  PIN y[245]
    DIRECTION INPUT ;
    USE SIGNAL ;
    PORT
      LAYER M4 ;
        RECT  0 120.384 0.084 120.408 ;
    END
  END y[245]
  PIN y[246]
    DIRECTION INPUT ;
    USE SIGNAL ;
    PORT
      LAYER M4 ;
        RECT  0 120.864 0.084 120.888 ;
    END
  END y[246]
  PIN y[247]
    DIRECTION INPUT ;
    USE SIGNAL ;
    PORT
      LAYER M4 ;
        RECT  0 121.344 0.084 121.368 ;
    END
  END y[247]
  PIN y[248]
    DIRECTION INPUT ;
    USE SIGNAL ;
    PORT
      LAYER M4 ;
        RECT  0 121.824 0.084 121.848 ;
    END
  END y[248]
  PIN y[249]
    DIRECTION INPUT ;
    USE SIGNAL ;
    PORT
      LAYER M4 ;
        RECT  0 122.208 0.084 122.232 ;
    END
  END y[249]
  PIN y[24]
    DIRECTION INPUT ;
    USE SIGNAL ;
    PORT
      LAYER M4 ;
        RECT  0 17.568 0.084 17.592 ;
    END
  END y[24]
  PIN y[250]
    DIRECTION INPUT ;
    USE SIGNAL ;
    PORT
      LAYER M4 ;
        RECT  0 122.688 0.084 122.712 ;
    END
  END y[250]
  PIN y[251]
    DIRECTION INPUT ;
    USE SIGNAL ;
    PORT
      LAYER M4 ;
        RECT  0 123.168 0.084 123.192 ;
    END
  END y[251]
  PIN y[252]
    DIRECTION INPUT ;
    USE SIGNAL ;
    PORT
      LAYER M4 ;
        RECT  0 123.648 0.084 123.672 ;
    END
  END y[252]
  PIN y[253]
    DIRECTION INPUT ;
    USE SIGNAL ;
    PORT
      LAYER M4 ;
        RECT  0 124.128 0.084 124.152 ;
    END
  END y[253]
  PIN y[254]
    DIRECTION INPUT ;
    USE SIGNAL ;
    PORT
      LAYER M4 ;
        RECT  0 124.608 0.084 124.632 ;
    END
  END y[254]
  PIN y[255]
    DIRECTION INPUT ;
    USE SIGNAL ;
    PORT
      LAYER M4 ;
        RECT  0 124.992 0.084 125.016 ;
    END
  END y[255]
  PIN y[25]
    DIRECTION INPUT ;
    USE SIGNAL ;
    PORT
      LAYER M4 ;
        RECT  0 18.048 0.084 18.072 ;
    END
  END y[25]
  PIN y[26]
    DIRECTION INPUT ;
    USE SIGNAL ;
    PORT
      LAYER M4 ;
        RECT  0 18.528 0.084 18.552 ;
    END
  END y[26]
  PIN y[27]
    DIRECTION INPUT ;
    USE SIGNAL ;
    PORT
      LAYER M4 ;
        RECT  0 19.008 0.084 19.032 ;
    END
  END y[27]
  PIN y[28]
    DIRECTION INPUT ;
    USE SIGNAL ;
    PORT
      LAYER M4 ;
        RECT  0 19.392 0.084 19.416 ;
    END
  END y[28]
  PIN y[29]
    DIRECTION INPUT ;
    USE SIGNAL ;
    PORT
      LAYER M4 ;
        RECT  0 19.872 0.084 19.896 ;
    END
  END y[29]
  PIN y[2]
    DIRECTION INPUT ;
    USE SIGNAL ;
    PORT
      LAYER M4 ;
        RECT  0 7.296 0.084 7.32 ;
    END
  END y[2]
  PIN y[30]
    DIRECTION INPUT ;
    USE SIGNAL ;
    PORT
      LAYER M4 ;
        RECT  0 20.352 0.084 20.376 ;
    END
  END y[30]
  PIN y[31]
    DIRECTION INPUT ;
    USE SIGNAL ;
    PORT
      LAYER M4 ;
        RECT  0 20.832 0.084 20.856 ;
    END
  END y[31]
  PIN y[32]
    DIRECTION INPUT ;
    USE SIGNAL ;
    PORT
      LAYER M4 ;
        RECT  0 21.312 0.084 21.336 ;
    END
  END y[32]
  PIN y[33]
    DIRECTION INPUT ;
    USE SIGNAL ;
    PORT
      LAYER M4 ;
        RECT  0 21.792 0.084 21.816 ;
    END
  END y[33]
  PIN y[34]
    DIRECTION INPUT ;
    USE SIGNAL ;
    PORT
      LAYER M4 ;
        RECT  0 22.176 0.084 22.2 ;
    END
  END y[34]
  PIN y[35]
    DIRECTION INPUT ;
    USE SIGNAL ;
    PORT
      LAYER M4 ;
        RECT  0 22.656 0.084 22.68 ;
    END
  END y[35]
  PIN y[36]
    DIRECTION INPUT ;
    USE SIGNAL ;
    PORT
      LAYER M4 ;
        RECT  0 23.136 0.084 23.16 ;
    END
  END y[36]
  PIN y[37]
    DIRECTION INPUT ;
    USE SIGNAL ;
    PORT
      LAYER M4 ;
        RECT  0 23.616 0.084 23.64 ;
    END
  END y[37]
  PIN y[38]
    DIRECTION INPUT ;
    USE SIGNAL ;
    PORT
      LAYER M4 ;
        RECT  0 24.096 0.084 24.12 ;
    END
  END y[38]
  PIN y[39]
    DIRECTION INPUT ;
    USE SIGNAL ;
    PORT
      LAYER M4 ;
        RECT  0 24.576 0.084 24.6 ;
    END
  END y[39]
  PIN y[3]
    DIRECTION INPUT ;
    USE SIGNAL ;
    PORT
      LAYER M4 ;
        RECT  0 7.776 0.084 7.8 ;
    END
  END y[3]
  PIN y[40]
    DIRECTION INPUT ;
    USE SIGNAL ;
    PORT
      LAYER M4 ;
        RECT  0 25.056 0.084 25.08 ;
    END
  END y[40]
  PIN y[41]
    DIRECTION INPUT ;
    USE SIGNAL ;
    PORT
      LAYER M4 ;
        RECT  0 25.44 0.084 25.464 ;
    END
  END y[41]
  PIN y[42]
    DIRECTION INPUT ;
    USE SIGNAL ;
    PORT
      LAYER M4 ;
        RECT  0 25.92 0.084 25.944 ;
    END
  END y[42]
  PIN y[43]
    DIRECTION INPUT ;
    USE SIGNAL ;
    PORT
      LAYER M4 ;
        RECT  0 26.4 0.084 26.424 ;
    END
  END y[43]
  PIN y[44]
    DIRECTION INPUT ;
    USE SIGNAL ;
    PORT
      LAYER M4 ;
        RECT  0 26.88 0.084 26.904 ;
    END
  END y[44]
  PIN y[45]
    DIRECTION INPUT ;
    USE SIGNAL ;
    PORT
      LAYER M4 ;
        RECT  0 27.36 0.084 27.384 ;
    END
  END y[45]
  PIN y[46]
    DIRECTION INPUT ;
    USE SIGNAL ;
    PORT
      LAYER M4 ;
        RECT  0 27.84 0.084 27.864 ;
    END
  END y[46]
  PIN y[47]
    DIRECTION INPUT ;
    USE SIGNAL ;
    PORT
      LAYER M4 ;
        RECT  0 28.224 0.084 28.248 ;
    END
  END y[47]
  PIN y[48]
    DIRECTION INPUT ;
    USE SIGNAL ;
    PORT
      LAYER M4 ;
        RECT  0 28.704 0.084 28.728 ;
    END
  END y[48]
  PIN y[49]
    DIRECTION INPUT ;
    USE SIGNAL ;
    PORT
      LAYER M4 ;
        RECT  0 29.184 0.084 29.208 ;
    END
  END y[49]
  PIN y[4]
    DIRECTION INPUT ;
    USE SIGNAL ;
    PORT
      LAYER M4 ;
        RECT  0 8.256 0.084 8.28 ;
    END
  END y[4]
  PIN y[50]
    DIRECTION INPUT ;
    USE SIGNAL ;
    PORT
      LAYER M4 ;
        RECT  0 29.664 0.084 29.688 ;
    END
  END y[50]
  PIN y[51]
    DIRECTION INPUT ;
    USE SIGNAL ;
    PORT
      LAYER M4 ;
        RECT  0 30.144 0.084 30.168 ;
    END
  END y[51]
  PIN y[52]
    DIRECTION INPUT ;
    USE SIGNAL ;
    PORT
      LAYER M4 ;
        RECT  0 30.624 0.084 30.648 ;
    END
  END y[52]
  PIN y[53]
    DIRECTION INPUT ;
    USE SIGNAL ;
    PORT
      LAYER M4 ;
        RECT  0 31.104 0.084 31.128 ;
    END
  END y[53]
  PIN y[54]
    DIRECTION INPUT ;
    USE SIGNAL ;
    PORT
      LAYER M4 ;
        RECT  0 31.488 0.084 31.512 ;
    END
  END y[54]
  PIN y[55]
    DIRECTION INPUT ;
    USE SIGNAL ;
    PORT
      LAYER M4 ;
        RECT  0 31.968 0.084 31.992 ;
    END
  END y[55]
  PIN y[56]
    DIRECTION INPUT ;
    USE SIGNAL ;
    PORT
      LAYER M4 ;
        RECT  0 32.448 0.084 32.472 ;
    END
  END y[56]
  PIN y[57]
    DIRECTION INPUT ;
    USE SIGNAL ;
    PORT
      LAYER M4 ;
        RECT  0 32.928 0.084 32.952 ;
    END
  END y[57]
  PIN y[58]
    DIRECTION INPUT ;
    USE SIGNAL ;
    PORT
      LAYER M4 ;
        RECT  0 33.408 0.084 33.432 ;
    END
  END y[58]
  PIN y[59]
    DIRECTION INPUT ;
    USE SIGNAL ;
    PORT
      LAYER M4 ;
        RECT  0 33.888 0.084 33.912 ;
    END
  END y[59]
  PIN y[5]
    DIRECTION INPUT ;
    USE SIGNAL ;
    PORT
      LAYER M4 ;
        RECT  0 8.736 0.084 8.76 ;
    END
  END y[5]
  PIN y[60]
    DIRECTION INPUT ;
    USE SIGNAL ;
    PORT
      LAYER M4 ;
        RECT  0 34.272 0.084 34.296 ;
    END
  END y[60]
  PIN y[61]
    DIRECTION INPUT ;
    USE SIGNAL ;
    PORT
      LAYER M4 ;
        RECT  0 34.752 0.084 34.776 ;
    END
  END y[61]
  PIN y[62]
    DIRECTION INPUT ;
    USE SIGNAL ;
    PORT
      LAYER M4 ;
        RECT  0 35.232 0.084 35.256 ;
    END
  END y[62]
  PIN y[63]
    DIRECTION INPUT ;
    USE SIGNAL ;
    PORT
      LAYER M4 ;
        RECT  0 35.712 0.084 35.736 ;
    END
  END y[63]
  PIN y[64]
    DIRECTION INPUT ;
    USE SIGNAL ;
    PORT
      LAYER M4 ;
        RECT  0 36.192 0.084 36.216 ;
    END
  END y[64]
  PIN y[65]
    DIRECTION INPUT ;
    USE SIGNAL ;
    PORT
      LAYER M4 ;
        RECT  0 36.672 0.084 36.696 ;
    END
  END y[65]
  PIN y[66]
    DIRECTION INPUT ;
    USE SIGNAL ;
    PORT
      LAYER M4 ;
        RECT  0 37.152 0.084 37.176 ;
    END
  END y[66]
  PIN y[67]
    DIRECTION INPUT ;
    USE SIGNAL ;
    PORT
      LAYER M4 ;
        RECT  0 37.536 0.084 37.56 ;
    END
  END y[67]
  PIN y[68]
    DIRECTION INPUT ;
    USE SIGNAL ;
    PORT
      LAYER M4 ;
        RECT  0 38.016 0.084 38.04 ;
    END
  END y[68]
  PIN y[69]
    DIRECTION INPUT ;
    USE SIGNAL ;
    PORT
      LAYER M4 ;
        RECT  0 38.496 0.084 38.52 ;
    END
  END y[69]
  PIN y[6]
    DIRECTION INPUT ;
    USE SIGNAL ;
    PORT
      LAYER M4 ;
        RECT  0 9.216 0.084 9.24 ;
    END
  END y[6]
  PIN y[70]
    DIRECTION INPUT ;
    USE SIGNAL ;
    PORT
      LAYER M4 ;
        RECT  0 38.976 0.084 39 ;
    END
  END y[70]
  PIN y[71]
    DIRECTION INPUT ;
    USE SIGNAL ;
    PORT
      LAYER M4 ;
        RECT  0 39.456 0.084 39.48 ;
    END
  END y[71]
  PIN y[72]
    DIRECTION INPUT ;
    USE SIGNAL ;
    PORT
      LAYER M4 ;
        RECT  0 39.936 0.084 39.96 ;
    END
  END y[72]
  PIN y[73]
    DIRECTION INPUT ;
    USE SIGNAL ;
    PORT
      LAYER M4 ;
        RECT  0 40.32 0.084 40.344 ;
    END
  END y[73]
  PIN y[74]
    DIRECTION INPUT ;
    USE SIGNAL ;
    PORT
      LAYER M4 ;
        RECT  0 40.8 0.084 40.824 ;
    END
  END y[74]
  PIN y[75]
    DIRECTION INPUT ;
    USE SIGNAL ;
    PORT
      LAYER M4 ;
        RECT  0 41.28 0.084 41.304 ;
    END
  END y[75]
  PIN y[76]
    DIRECTION INPUT ;
    USE SIGNAL ;
    PORT
      LAYER M4 ;
        RECT  0 41.76 0.084 41.784 ;
    END
  END y[76]
  PIN y[77]
    DIRECTION INPUT ;
    USE SIGNAL ;
    PORT
      LAYER M4 ;
        RECT  0 42.24 0.084 42.264 ;
    END
  END y[77]
  PIN y[78]
    DIRECTION INPUT ;
    USE SIGNAL ;
    PORT
      LAYER M4 ;
        RECT  0 42.72 0.084 42.744 ;
    END
  END y[78]
  PIN y[79]
    DIRECTION INPUT ;
    USE SIGNAL ;
    PORT
      LAYER M4 ;
        RECT  0 43.2 0.084 43.224 ;
    END
  END y[79]
  PIN y[7]
    DIRECTION INPUT ;
    USE SIGNAL ;
    PORT
      LAYER M4 ;
        RECT  0 9.696 0.084 9.72 ;
    END
  END y[7]
  PIN y[80]
    DIRECTION INPUT ;
    USE SIGNAL ;
    PORT
      LAYER M4 ;
        RECT  0 43.584 0.084 43.608 ;
    END
  END y[80]
  PIN y[81]
    DIRECTION INPUT ;
    USE SIGNAL ;
    PORT
      LAYER M4 ;
        RECT  0 44.064 0.084 44.088 ;
    END
  END y[81]
  PIN y[82]
    DIRECTION INPUT ;
    USE SIGNAL ;
    PORT
      LAYER M4 ;
        RECT  0 44.544 0.084 44.568 ;
    END
  END y[82]
  PIN y[83]
    DIRECTION INPUT ;
    USE SIGNAL ;
    PORT
      LAYER M4 ;
        RECT  0 45.024 0.084 45.048 ;
    END
  END y[83]
  PIN y[84]
    DIRECTION INPUT ;
    USE SIGNAL ;
    PORT
      LAYER M4 ;
        RECT  0 45.504 0.084 45.528 ;
    END
  END y[84]
  PIN y[85]
    DIRECTION INPUT ;
    USE SIGNAL ;
    PORT
      LAYER M4 ;
        RECT  0 45.984 0.084 46.008 ;
    END
  END y[85]
  PIN y[86]
    DIRECTION INPUT ;
    USE SIGNAL ;
    PORT
      LAYER M4 ;
        RECT  0 46.368 0.084 46.392 ;
    END
  END y[86]
  PIN y[87]
    DIRECTION INPUT ;
    USE SIGNAL ;
    PORT
      LAYER M4 ;
        RECT  0 46.848 0.084 46.872 ;
    END
  END y[87]
  PIN y[88]
    DIRECTION INPUT ;
    USE SIGNAL ;
    PORT
      LAYER M4 ;
        RECT  0 47.328 0.084 47.352 ;
    END
  END y[88]
  PIN y[89]
    DIRECTION INPUT ;
    USE SIGNAL ;
    PORT
      LAYER M4 ;
        RECT  0 47.808 0.084 47.832 ;
    END
  END y[89]
  PIN y[8]
    DIRECTION INPUT ;
    USE SIGNAL ;
    PORT
      LAYER M4 ;
        RECT  0 10.08 0.084 10.104 ;
    END
  END y[8]
  PIN y[90]
    DIRECTION INPUT ;
    USE SIGNAL ;
    PORT
      LAYER M4 ;
        RECT  0 48.288 0.084 48.312 ;
    END
  END y[90]
  PIN y[91]
    DIRECTION INPUT ;
    USE SIGNAL ;
    PORT
      LAYER M4 ;
        RECT  0 48.768 0.084 48.792 ;
    END
  END y[91]
  PIN y[92]
    DIRECTION INPUT ;
    USE SIGNAL ;
    PORT
      LAYER M4 ;
        RECT  0 49.248 0.084 49.272 ;
    END
  END y[92]
  PIN y[93]
    DIRECTION INPUT ;
    USE SIGNAL ;
    PORT
      LAYER M4 ;
        RECT  0 49.632 0.084 49.656 ;
    END
  END y[93]
  PIN y[94]
    DIRECTION INPUT ;
    USE SIGNAL ;
    PORT
      LAYER M4 ;
        RECT  0 50.112 0.084 50.136 ;
    END
  END y[94]
  PIN y[95]
    DIRECTION INPUT ;
    USE SIGNAL ;
    PORT
      LAYER M4 ;
        RECT  0 50.592 0.084 50.616 ;
    END
  END y[95]
  PIN y[96]
    DIRECTION INPUT ;
    USE SIGNAL ;
    PORT
      LAYER M4 ;
        RECT  0 51.072 0.084 51.096 ;
    END
  END y[96]
  PIN y[97]
    DIRECTION INPUT ;
    USE SIGNAL ;
    PORT
      LAYER M4 ;
        RECT  0 51.552 0.084 51.576 ;
    END
  END y[97]
  PIN y[98]
    DIRECTION INPUT ;
    USE SIGNAL ;
    PORT
      LAYER M4 ;
        RECT  0 52.032 0.084 52.056 ;
    END
  END y[98]
  PIN y[99]
    DIRECTION INPUT ;
    USE SIGNAL ;
    PORT
      LAYER M4 ;
        RECT  0 52.416 0.084 52.44 ;
    END
  END y[99]
  PIN y[9]
    DIRECTION INPUT ;
    USE SIGNAL ;
    PORT
      LAYER M4 ;
        RECT  0 10.56 0.084 10.584 ;
    END
  END y[9]
  PIN y_i[0]
    DIRECTION INPUT ;
    USE SIGNAL ;
    PORT
      LAYER M4 ;
        RECT  0 4.992 0.084 5.016 ;
    END
  END y_i[0]
  PIN y_i[1]
    DIRECTION INPUT ;
    USE SIGNAL ;
    PORT
      LAYER M4 ;
        RECT  0 5.472 0.084 5.496 ;
    END
  END y_i[1]
  PIN y_i[2]
    DIRECTION INPUT ;
    USE SIGNAL ;
    PORT
      LAYER M4 ;
        RECT  0 5.952 0.084 5.976 ;
    END
  END y_i[2]
  PIN y_v
    DIRECTION INPUT ;
    USE SIGNAL ;
    PORT
      LAYER M4 ;
        RECT  0 4.512 0.084 4.536 ;
    END
  END y_v
  PIN VDD
    DIRECTION INOUT ;
    USE POWER ;
    PORT
      LAYER M5 ;
        RECT  166.356 4.311 166.476 125.289 ;
        RECT  162.036 4.311 162.156 125.289 ;
        RECT  157.716 4.311 157.836 125.289 ;
        RECT  153.396 4.311 153.516 125.289 ;
        RECT  149.076 4.311 149.196 125.289 ;
        RECT  144.756 4.311 144.876 125.289 ;
        RECT  140.436 4.311 140.556 125.289 ;
        RECT  136.116 4.311 136.236 125.289 ;
        RECT  131.796 4.311 131.916 125.289 ;
        RECT  127.476 4.311 127.596 125.289 ;
        RECT  123.156 4.311 123.276 125.289 ;
        RECT  118.836 4.311 118.956 125.289 ;
        RECT  114.516 4.311 114.636 125.289 ;
        RECT  110.196 4.311 110.316 125.289 ;
        RECT  105.876 4.311 105.996 125.289 ;
        RECT  101.556 4.311 101.676 125.289 ;
        RECT  97.236 4.311 97.356 125.289 ;
        RECT  92.916 4.311 93.036 125.289 ;
        RECT  88.596 4.311 88.716 125.289 ;
        RECT  84.276 4.311 84.396 125.289 ;
        RECT  79.956 4.311 80.076 125.289 ;
        RECT  75.636 4.311 75.756 125.289 ;
        RECT  71.316 4.311 71.436 125.289 ;
        RECT  66.996 4.311 67.116 125.289 ;
        RECT  62.676 4.311 62.796 125.289 ;
        RECT  58.356 4.311 58.476 125.289 ;
        RECT  54.036 4.311 54.156 125.289 ;
        RECT  49.716 4.311 49.836 125.289 ;
        RECT  45.396 4.311 45.516 125.289 ;
        RECT  41.076 4.311 41.196 125.289 ;
        RECT  36.756 4.311 36.876 125.289 ;
        RECT  32.436 4.311 32.556 125.289 ;
        RECT  28.116 4.311 28.236 125.289 ;
        RECT  23.796 4.311 23.916 125.289 ;
        RECT  19.476 4.311 19.596 125.289 ;
        RECT  15.156 4.311 15.276 125.289 ;
        RECT  10.836 4.311 10.956 125.289 ;
        RECT  6.516 4.311 6.636 125.289 ;
    END
  END VDD
  PIN VSS
    DIRECTION INOUT ;
    USE GROUND ;
    PORT
      LAYER M5 ;
        RECT  166.164 4.297 166.284 125.303 ;
        RECT  161.844 4.297 161.964 125.303 ;
        RECT  157.524 4.297 157.644 125.303 ;
        RECT  153.204 4.297 153.324 125.303 ;
        RECT  148.884 4.297 149.004 125.303 ;
        RECT  144.564 4.297 144.684 125.303 ;
        RECT  140.244 4.297 140.364 125.303 ;
        RECT  135.924 4.311 136.044 125.303 ;
        RECT  131.604 4.311 131.724 125.303 ;
        RECT  127.284 4.311 127.404 125.303 ;
        RECT  122.964 4.311 123.084 125.303 ;
        RECT  118.644 4.311 118.764 125.303 ;
        RECT  114.324 4.311 114.444 125.303 ;
        RECT  110.004 4.311 110.124 125.303 ;
        RECT  105.684 4.311 105.804 125.303 ;
        RECT  101.364 4.311 101.484 125.303 ;
        RECT  97.044 4.311 97.164 125.303 ;
        RECT  92.724 4.311 92.844 125.303 ;
        RECT  88.404 4.311 88.524 125.303 ;
        RECT  84.084 4.311 84.204 125.303 ;
        RECT  79.764 4.311 79.884 125.303 ;
        RECT  75.444 4.311 75.564 125.303 ;
        RECT  71.124 4.311 71.244 125.303 ;
        RECT  66.804 4.311 66.924 125.303 ;
        RECT  62.484 4.311 62.604 125.303 ;
        RECT  58.164 4.311 58.284 125.303 ;
        RECT  53.844 4.311 53.964 125.303 ;
        RECT  49.524 4.311 49.644 125.303 ;
        RECT  45.204 4.311 45.324 125.303 ;
        RECT  40.884 4.311 41.004 125.303 ;
        RECT  36.564 4.311 36.684 125.303 ;
        RECT  32.244 4.297 32.364 125.303 ;
        RECT  27.924 4.297 28.044 125.303 ;
        RECT  23.604 4.297 23.724 125.303 ;
        RECT  19.284 4.297 19.404 125.303 ;
        RECT  14.964 4.297 15.084 125.303 ;
        RECT  10.644 4.297 10.764 125.303 ;
        RECT  6.324 4.297 6.444 125.303 ;
    END
  END VSS
  OBS
    LAYER RVTN ;
     RECT  0 1.111 172.8 129.6 ;
    LAYER RVTP ;
     RECT  0 1.111 172.8 129.6 ;
    LAYER M1 ;
     RECT  0 1.111 172.8 129.6 ;
    LAYER M2 ;
     RECT  0 1.111 172.8 129.6 ;
    LAYER M3 ;
     RECT  0 1.111 172.8 129.6 ;
    LAYER M4 ;
     RECT  0 1.111 172.8 129.6 ;
    LAYER M5 ;
     RECT  0 1.111 172.8 129.6 ;
  END
END ot_s81sl_vq
END LIBRARY
